# BSD 3-Clause License
#
# Copyright (c) 2026 <Sungwoo Jung, Cheng-Yu Tsai, Amaan Rahman, Junsik Yoon, Sandra Maria Shaji, Sung Kyu Lim >, University of Southern California
#
# Redistribution and use in source and binary forms, with or without
# modification, are permitted under the BSD 3-Clause License.
# See the LICENSE file in the project root for full license terms.


VERSION 5.8 ;
BUSBITCHARS "[]" ;
DIVIDERCHAR "/" ;

UNITS
  DATABASE MICRONS 10000 ;
END UNITS

MANUFACTURINGGRID 0.0001 ;

PROPERTYDEFINITIONS
  MACRO snapMode STRING ;
  MACRO segSnapMode STRING ;
  MACRO dimmingIntensity INTEGER ;
  MACRO arrayDisplay STRING ;
  MACRO displayResolution STRING ;
  MACRO instanceDrawingMode STRING ;
  MACRO autoZoomScale INTEGER ;
  MACRO filterSizeDrawingStyle STRING ;
  MACRO dimmingScope STRING ;
  MACRO filterSize REAL ;
  MACRO scrollPercent INTEGER ;
  MACRO gridMultiple INTEGER ;
  MACRO gridSpacing REAL ;
  MACRO xSnapSpacing REAL ;
  MACRO instLabel STRING ;
  MACRO autoZoomMode STRING ;
  MACRO lppVisibilityMode STRING ;
  MACRO stopLevel INTEGER ;
  MACRO mergeScope STRING ;
  MACRO ySnapSpacing REAL ;
  MACRO startLevel INTEGER ;
  MACRO pathCL STRING ;
END PROPERTYDEFINITIONS

LAYER well
  TYPE MASTERSLICE ;
END well

LAYER Gate
  TYPE MASTERSLICE ;
END Gate

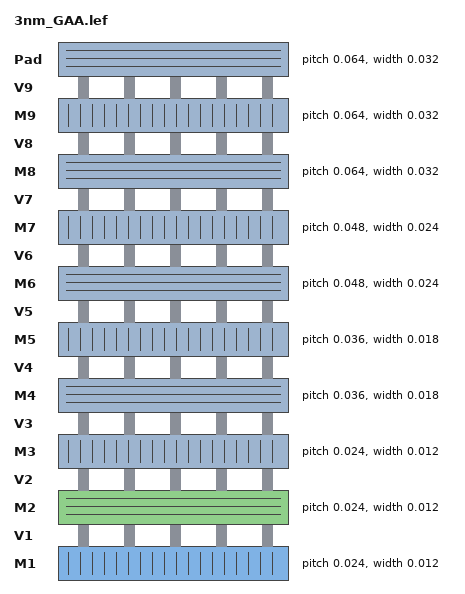
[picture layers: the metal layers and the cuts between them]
LAYER M1
  TYPE ROUTING ;
  DIRECTION VERTICAL ;
  PITCH 0.024 ;
  WIDTH 0.012 ;
  PROPERTY LEF58_WIDTH "WIDTH 0.012 WRONGDIRECTION ;" ;
END M1

LAYER V1
  TYPE CUT ;
END V1

LAYER M2
  TYPE ROUTING ;
  DIRECTION HORIZONTAL ;
  PITCH 0.024 ;
  WIDTH 0.012 ;
  PROPERTY LEF58_WIDTH "WIDTH 0.012 WRONGDIRECTION ;" ;
END M2

LAYER V2
  TYPE CUT ;
END V2

LAYER M3
  TYPE ROUTING ;
  DIRECTION VERTICAL ;
  PITCH 0.024 ;
  WIDTH 0.012 ;
  PROPERTY LEF58_WIDTH "WIDTH 0.012 WRONGDIRECTION ;" ;
END M3

LAYER V3
  TYPE CUT ;
END V3

LAYER M4
  TYPE ROUTING ;
  DIRECTION HORIZONTAL ;
  PITCH 0.036 ;
  WIDTH 0.018 ;
  PROPERTY LEF58_WIDTH "WIDTH 0.018 WRONGDIRECTION ;" ;
END M4

LAYER V4
  TYPE CUT ;
END V4

LAYER M5
  TYPE ROUTING ;
  DIRECTION VERTICAL ;
  PITCH 0.036 ;
  WIDTH 0.018 ;
  PROPERTY LEF58_WIDTH "WIDTH 0.018 WRONGDIRECTION ;" ;
END M5

LAYER V5
  TYPE CUT ;
END V5

LAYER M6
  TYPE ROUTING ;
  DIRECTION HORIZONTAL ;
  PITCH 0.048 ;
  WIDTH 0.024 ;
  PROPERTY LEF58_WIDTH "WIDTH 0.024 WRONGDIRECTION ;" ;
END M6

LAYER V6
  TYPE CUT ;
END V6

LAYER M7
  TYPE ROUTING ;
  DIRECTION VERTICAL ;
  PITCH 0.048 ;
  WIDTH 0.024 ;
  PROPERTY LEF58_WIDTH "WIDTH 0.024 WRONGDIRECTION ;" ;
END M7

LAYER V7
  TYPE CUT ;
END V7

LAYER M8
  TYPE ROUTING ;
  DIRECTION HORIZONTAL ;
  PITCH 0.064 ;
  WIDTH 0.032 ;
  PROPERTY LEF58_WIDTH "WIDTH 0.032 WRONGDIRECTION ;" ;
END M8

LAYER V8
  TYPE CUT ;
END V8

LAYER M9
  TYPE ROUTING ;
  DIRECTION VERTICAL ;
  PITCH 0.064 ;
  WIDTH 0.032 ;
  PROPERTY LEF58_WIDTH "WIDTH 0.032 WRONGDIRECTION ;" ;
END M9

LAYER V9
  TYPE CUT ;
END V9

LAYER Pad
  TYPE ROUTING ;
  DIRECTION HORIZONTAL ;
  PITCH 0.064 ;
  WIDTH 0.032 ;
  PROPERTY LEF58_WIDTH "WIDTH 0.032 WRONGDIRECTION ;" ;
END Pad

LAYER Active
  TYPE MASTERSLICE ;
END Active

LAYER fin
  TYPE MASTERSLICE ;
END fin

LAYER P_SUB
  TYPE MASTERSLICE ;
END P_SUB

LAYER Dummy
  TYPE MASTERSLICE ;
END Dummy

LAYER GCut
  TYPE MASTERSLICE ;
END GCut

LAYER Nselect
  TYPE MASTERSLICE ;
END Nselect

LAYER Pselect
  TYPE MASTERSLICE ;
END Pselect

LAYER SDT
  TYPE MASTERSLICE ;
END SDT

LAYER LIG
  TYPE MASTERSLICE ;
END LIG

LAYER LISD
  TYPE MASTERSLICE ;
END LISD

LAYER V0
  TYPE MASTERSLICE ;
END V0

LAYER SLVT
  TYPE MASTERSLICE ;
END SLVT

LAYER LVT
  TYPE MASTERSLICE ;
END LVT

LAYER SRAMDRC
  TYPE MASTERSLICE ;
END SRAMDRC

LAYER BOUNDARY
  TYPE MASTERSLICE ;
END BOUNDARY

LAYER TEXT
  TYPE MASTERSLICE ;
END TEXT

LAYER SRAMVT
  TYPE MASTERSLICE ;
END SRAMVT

LAYER text
  TYPE MASTERSLICE ;
END text

VIA Pad_M9
  LAYER M9 ;
    RECT -0.016 -0.025 0.016 0.025 ;
  LAYER V9 ;
    RECT -0.016 -0.016 0.016 0.016 ;
  LAYER Pad ;
    RECT -0.027 -0.016 0.027 0.016 ;
END Pad_M9

VIA M9_M8
  LAYER M8 ;
    RECT -0.025 -0.016 0.025 0.016 ;
  LAYER V8 ;
    RECT -0.016 -0.016 0.016 0.016 ;
  LAYER M9 ;
    RECT -0.016 -0.025 0.016 0.025 ;
END M9_M8

VIA M8_M7
  LAYER M7 ;
    RECT -0.012 -0.019 0.012 0.019 ;
  LAYER V7 ;
    RECT -0.012 -0.012 0.012 0.012 ;
  LAYER M8 ;
    RECT -0.021 -0.012 0.021 0.012 ;
END M8_M7

VIA M7_M6
  LAYER M6 ;
    RECT -0.019 -0.012 0.019 0.012 ;
  LAYER V6 ;
    RECT -0.012 -0.012 0.012 0.012 ;
  LAYER M7 ;
    RECT -0.012 -0.019 0.012 0.019 ;
END M7_M6

VIA M6_M5
  LAYER M5 ;
    RECT -0.009 -0.014 0.009 0.014 ;
  LAYER V5 ;
    RECT -0.009 -0.009 0.009 0.009 ;
  LAYER M6 ;
    RECT -0.016 -0.009 0.016 0.009 ;
END M6_M5

VIA M5_M4
  LAYER M4 ;
    RECT -0.014 -0.009 0.014 0.009 ;
  LAYER V4 ;
    RECT -0.009 -0.009 0.009 0.009 ;
  LAYER M5 ;
    RECT -0.009 -0.014 0.009 0.014 ;
END M5_M4

VIA M4_M3
  LAYER M3 ;
    RECT -0.006 -0.009 0.006 0.009 ;
  LAYER V3 ;
    RECT -0.006 -0.006 0.006 0.006 ;
  LAYER M4 ;
    RECT -0.011 -0.006 0.011 0.006 ;
END M4_M3

VIA M3_M2
  LAYER M2 ;
    RECT -0.009 -0.006 0.009 0.006 ;
  LAYER V2 ;
    RECT -0.006 -0.006 0.006 0.006 ;
  LAYER M3 ;
    RECT -0.006 -0.009 0.006 0.009 ;
END M3_M2

VIA M2_M1
  LAYER M1 ;
    RECT -0.006 -0.009 0.006 0.009 ;
  LAYER V1 ;
    RECT -0.006 -0.006 0.006 0.006 ;
  LAYER M2 ;
    RECT -0.009 -0.006 0.009 0.006 ;
END M2_M1

SITE core
  CLASS CORE ;
  SIZE 0.042 BY 0.144 ;
END core

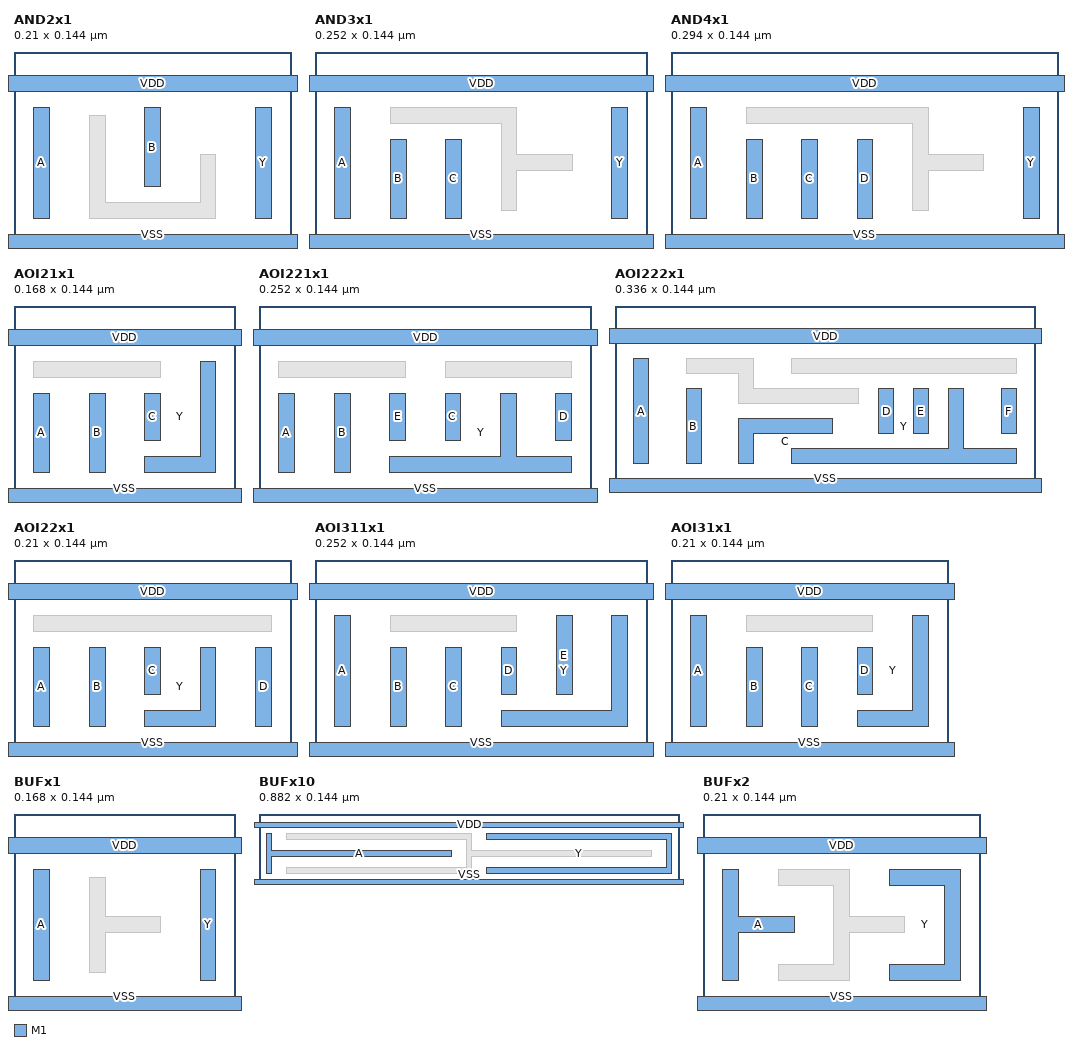
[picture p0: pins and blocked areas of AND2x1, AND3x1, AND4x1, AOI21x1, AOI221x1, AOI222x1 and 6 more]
MACRO AND2x1
  CLASS CORE ;
  FOREIGN AND2x1 ;
  ORIGIN 0 0 ;
  SIZE 0.21 BY 0.144 ;
  SYMMETRY X Y ;
  SITE core ;
  PIN A
    DIRECTION INPUT ;
    USE SIGNAL ;
    PORT
      LAYER M1 ;
        RECT 0.015 0.018 0.027 0.102 ;
    END
  END A
  PIN B
    DIRECTION INPUT ;
    USE SIGNAL ;
    PORT
      LAYER M1 ;
        RECT 0.099 0.042 0.111 0.102 ;
    END
  END B
  PIN Y
    DIRECTION OUTPUT ;
    USE SIGNAL ;
    PORT
      LAYER M1 ;
        RECT 0.183 0.018 0.195 0.102 ;
    END
  END Y
  PIN VDD
    DIRECTION INOUT ;
    USE POWER ;
    PORT
      LAYER M1 ;
        RECT -0.009 0.114 0.219 0.126 ;
    END
  END VDD
  PIN VSS
    DIRECTION INOUT ;
    USE GROUND ;
    PORT
      LAYER M1 ;
        RECT -0.009 -0.006 0.219 0.006 ;
    END
  END VSS
  OBS
    LAYER M1 ;
      POLYGON 0.069 0.096 0.069 0.03 0.141 0.03 0.141 0.066 0.153 0.066 0.153 0.018 0.057 0.018 0.057 0.096 ;
  END
END AND2x1

MACRO AND3x1
  CLASS CORE ;
  FOREIGN AND3x1 ;
  ORIGIN 0 0 ;
  SIZE 0.252 BY 0.144 ;
  SYMMETRY X Y ;
  SITE core ;
  PIN A
    DIRECTION INPUT ;
    USE SIGNAL ;
    PORT
      LAYER M1 ;
        RECT 0.015 0.018 0.027 0.102 ;
    END
  END A
  PIN B
    DIRECTION INPUT ;
    USE SIGNAL ;
    PORT
      LAYER M1 ;
        RECT 0.057 0.018 0.069 0.078 ;
    END
  END B
  PIN C
    DIRECTION INPUT ;
    USE SIGNAL ;
    PORT
      LAYER M1 ;
        RECT 0.099 0.018 0.111 0.078 ;
    END
  END C
  PIN Y
    DIRECTION OUTPUT ;
    USE SIGNAL ;
    PORT
      LAYER M1 ;
        RECT 0.225 0.018 0.237 0.102 ;
    END
  END Y
  PIN VDD
    DIRECTION INOUT ;
    USE POWER ;
    PORT
      LAYER M1 ;
        RECT -0.009 0.114 0.261 0.126 ;
    END
  END VDD
  PIN VSS
    DIRECTION INOUT ;
    USE GROUND ;
    PORT
      LAYER M1 ;
        RECT -0.009 -0.006 0.261 0.006 ;
    END
  END VSS
  OBS
    LAYER M1 ;
      POLYGON 0.153 0.102 0.153 0.066 0.195 0.066 0.195 0.054 0.153 0.054 0.153 0.024 0.141 0.024 0.141 0.09 0.057 0.09 0.057 0.102 ;
  END
END AND3x1

MACRO AND4x1
  CLASS CORE ;
  FOREIGN AND4x1 ;
  ORIGIN 0 0 ;
  SIZE 0.294 BY 0.144 ;
  SYMMETRY X Y ;
  SITE core ;
  PIN A
    DIRECTION INPUT ;
    USE SIGNAL ;
    PORT
      LAYER M1 ;
        RECT 0.015 0.018 0.027 0.102 ;
    END
  END A
  PIN B
    DIRECTION INPUT ;
    USE SIGNAL ;
    PORT
      LAYER M1 ;
        RECT 0.057 0.018 0.069 0.078 ;
    END
  END B
  PIN C
    DIRECTION INPUT ;
    USE SIGNAL ;
    PORT
      LAYER M1 ;
        RECT 0.099 0.018 0.111 0.078 ;
    END
  END C
  PIN D
    DIRECTION INPUT ;
    USE SIGNAL ;
    PORT
      LAYER M1 ;
        RECT 0.141 0.018 0.153 0.078 ;
    END
  END D
  PIN Y
    DIRECTION OUTPUT ;
    USE SIGNAL ;
    PORT
      LAYER M1 ;
        RECT 0.267 0.018 0.279 0.102 ;
    END
  END Y
  PIN VDD
    DIRECTION INOUT ;
    USE POWER ;
    PORT
      LAYER M1 ;
        RECT -0.009 0.114 0.303 0.126 ;
    END
  END VDD
  PIN VSS
    DIRECTION INOUT ;
    USE GROUND ;
    PORT
      LAYER M1 ;
        RECT -0.009 -0.006 0.303 0.006 ;
    END
  END VSS
  OBS
    LAYER M1 ;
      POLYGON 0.195 0.102 0.195 0.066 0.237 0.066 0.237 0.054 0.195 0.054 0.195 0.024 0.183 0.024 0.183 0.09 0.057 0.09 0.057 0.102 ;
  END
END AND4x1

MACRO AOI21x1
  CLASS CORE ;
  FOREIGN AOI21x1 ;
  ORIGIN 0 0 ;
  SIZE 0.168 BY 0.144 ;
  SYMMETRY X Y ;
  SITE core ;
  PIN A
    DIRECTION INPUT ;
    USE SIGNAL ;
    PORT
      LAYER M1 ;
        RECT 0.015 0.018 0.027 0.078 ;
    END
  END A
  PIN B
    DIRECTION INPUT ;
    USE SIGNAL ;
    PORT
      LAYER M1 ;
        RECT 0.057 0.018 0.069 0.078 ;
    END
  END B
  PIN C
    DIRECTION INPUT ;
    USE SIGNAL ;
    PORT
      LAYER M1 ;
        RECT 0.099 0.042 0.111 0.078 ;
    END
  END C
  PIN Y
    DIRECTION OUTPUT ;
    USE SIGNAL ;
    PORT
      LAYER M1 ;
        POLYGON 0.153 0.102 0.153 0.018 0.099 0.018 0.099 0.03 0.141 0.03 0.141 0.102 ;
    END
  END Y
  PIN VDD
    DIRECTION INOUT ;
    USE POWER ;
    PORT
      LAYER M1 ;
        RECT -0.009 0.114 0.177 0.126 ;
    END
  END VDD
  PIN VSS
    DIRECTION INOUT ;
    USE GROUND ;
    PORT
      LAYER M1 ;
        RECT -0.009 -0.006 0.177 0.006 ;
    END
  END VSS
  OBS
    LAYER M1 ;
      RECT 0.015 0.09 0.111 0.102 ;
  END
END AOI21x1

MACRO AOI221x1
  CLASS CORE ;
  FOREIGN AOI221x1 ;
  ORIGIN 0 0 ;
  SIZE 0.252 BY 0.144 ;
  SYMMETRY X Y ;
  SITE core ;
  PIN A
    DIRECTION INPUT ;
    USE SIGNAL ;
    PORT
      LAYER M1 ;
        RECT 0.015 0.018 0.027 0.078 ;
    END
  END A
  PIN B
    DIRECTION INPUT ;
    USE SIGNAL ;
    PORT
      LAYER M1 ;
        RECT 0.057 0.018 0.069 0.078 ;
    END
  END B
  PIN C
    DIRECTION INPUT ;
    USE SIGNAL ;
    PORT
      LAYER M1 ;
        RECT 0.141 0.042 0.153 0.078 ;
    END
  END C
  PIN D
    DIRECTION INPUT ;
    USE SIGNAL ;
    PORT
      LAYER M1 ;
        RECT 0.225 0.042 0.237 0.078 ;
    END
  END D
  PIN E
    DIRECTION INPUT ;
    USE SIGNAL ;
    PORT
      LAYER M1 ;
        RECT 0.099 0.042 0.111 0.078 ;
    END
  END E
  PIN Y
    DIRECTION OUTPUT ;
    USE SIGNAL ;
    PORT
      LAYER M1 ;
        POLYGON 0.195 0.078 0.195 0.03 0.237 0.03 0.237 0.018 0.099 0.018 0.099 0.03 0.183 0.03 0.183 0.078 ;
    END
  END Y
  PIN VDD
    DIRECTION INOUT ;
    USE POWER ;
    PORT
      LAYER M1 ;
        RECT -0.009 0.114 0.261 0.126 ;
    END
  END VDD
  PIN VSS
    DIRECTION INOUT ;
    USE GROUND ;
    PORT
      LAYER M1 ;
        RECT -0.009 -0.006 0.261 0.006 ;
    END
  END VSS
  OBS
    LAYER M1 ;
      RECT 0.141 0.09 0.237 0.102 ;
      RECT 0.015 0.09 0.111 0.102 ;
  END
END AOI221x1

MACRO AOI222x1
  CLASS CORE ;
  FOREIGN AOI222x1 ;
  ORIGIN 0 0 ;
  SIZE 0.336 BY 0.144 ;
  SYMMETRY X Y ;
  SITE core ;
  PIN A
    DIRECTION INPUT ;
    USE SIGNAL ;
    PORT
      LAYER M1 ;
        RECT 0.015 0.018 0.027 0.102 ;
    END
  END A
  PIN B
    DIRECTION INPUT ;
    USE SIGNAL ;
    PORT
      LAYER M1 ;
        RECT 0.057 0.018 0.069 0.078 ;
    END
  END B
  PIN C
    DIRECTION INPUT ;
    USE SIGNAL ;
    PORT
      LAYER M1 ;
        POLYGON 0.174 0.054 0.174 0.042 0.111 0.042 0.111 0.018 0.099 0.018 0.099 0.054 ;
    END
  END C
  PIN D
    DIRECTION INPUT ;
    USE SIGNAL ;
    PORT
      LAYER M1 ;
        RECT 0.211 0.042 0.223 0.078 ;
    END
  END D
  PIN E
    DIRECTION INPUT ;
    USE SIGNAL ;
    PORT
      LAYER M1 ;
        RECT 0.239 0.042 0.251 0.078 ;
    END
  END E
  PIN F
    DIRECTION INPUT ;
    USE SIGNAL ;
    PORT
      LAYER M1 ;
        RECT 0.309 0.042 0.321 0.078 ;
    END
  END F
  PIN Y
    DIRECTION OUTPUT ;
    USE SIGNAL ;
    PORT
      LAYER M1 ;
        POLYGON 0.279 0.078 0.279 0.03 0.321 0.03 0.321 0.018 0.141 0.018 0.141 0.03 0.267 0.03 0.267 0.078 ;
    END
  END Y
  PIN VDD
    DIRECTION INOUT ;
    USE POWER ;
    PORT
      LAYER M1 ;
        RECT -0.009 0.114 0.345 0.126 ;
    END
  END VDD
  PIN VSS
    DIRECTION INOUT ;
    USE GROUND ;
    PORT
      LAYER M1 ;
        RECT -0.009 -0.006 0.345 0.006 ;
    END
  END VSS
  OBS
    LAYER M1 ;
      RECT 0.141 0.09 0.321 0.102 ;
      POLYGON 0.111 0.102 0.111 0.078 0.195 0.078 0.195 0.066 0.099 0.066 0.099 0.09 0.057 0.09 0.057 0.102 ;
  END
END AOI222x1

MACRO AOI22x1
  CLASS CORE ;
  FOREIGN AOI22x1 ;
  ORIGIN 0 0 ;
  SIZE 0.21 BY 0.144 ;
  SYMMETRY X Y ;
  SITE core ;
  PIN A
    DIRECTION INPUT ;
    USE SIGNAL ;
    PORT
      LAYER M1 ;
        RECT 0.015 0.018 0.027 0.078 ;
    END
  END A
  PIN B
    DIRECTION INPUT ;
    USE SIGNAL ;
    PORT
      LAYER M1 ;
        RECT 0.057 0.018 0.069 0.078 ;
    END
  END B
  PIN C
    DIRECTION INPUT ;
    USE SIGNAL ;
    PORT
      LAYER M1 ;
        RECT 0.099 0.042 0.111 0.078 ;
    END
  END C
  PIN D
    DIRECTION INPUT ;
    USE SIGNAL ;
    PORT
      LAYER M1 ;
        RECT 0.183 0.018 0.195 0.078 ;
    END
  END D
  PIN Y
    DIRECTION OUTPUT ;
    USE SIGNAL ;
    PORT
      LAYER M1 ;
        POLYGON 0.153 0.078 0.153 0.018 0.099 0.018 0.099 0.03 0.141 0.03 0.141 0.078 ;
    END
  END Y
  PIN VDD
    DIRECTION INOUT ;
    USE POWER ;
    PORT
      LAYER M1 ;
        RECT -0.009 0.114 0.219 0.126 ;
    END
  END VDD
  PIN VSS
    DIRECTION INOUT ;
    USE GROUND ;
    PORT
      LAYER M1 ;
        RECT -0.009 -0.006 0.219 0.006 ;
    END
  END VSS
  OBS
    LAYER M1 ;
      RECT 0.015 0.09 0.195 0.102 ;
  END
END AOI22x1

MACRO AOI311x1
  CLASS CORE ;
  FOREIGN AOI311x1 ;
  ORIGIN 0 0 ;
  SIZE 0.252 BY 0.144 ;
  SYMMETRY X Y ;
  SITE core ;
  PIN A
    DIRECTION INPUT ;
    USE SIGNAL ;
    PORT
      LAYER M1 ;
        RECT 0.015 0.018 0.027 0.102 ;
    END
  END A
  PIN B
    DIRECTION INPUT ;
    USE SIGNAL ;
    PORT
      LAYER M1 ;
        RECT 0.057 0.018 0.069 0.078 ;
    END
  END B
  PIN C
    DIRECTION INPUT ;
    USE SIGNAL ;
    PORT
      LAYER M1 ;
        RECT 0.099 0.018 0.111 0.078 ;
    END
  END C
  PIN D
    DIRECTION INPUT ;
    USE SIGNAL ;
    PORT
      LAYER M1 ;
        RECT 0.141 0.042 0.153 0.078 ;
    END
  END D
  PIN E
    DIRECTION INPUT ;
    USE SIGNAL ;
    PORT
      LAYER M1 ;
        RECT 0.183 0.042 0.195 0.102 ;
    END
  END E
  PIN Y
    DIRECTION OUTPUT ;
    USE SIGNAL ;
    PORT
      LAYER M1 ;
        POLYGON 0.237 0.102 0.237 0.018 0.141 0.018 0.141 0.03 0.225 0.03 0.225 0.102 ;
    END
  END Y
  PIN VDD
    DIRECTION INOUT ;
    USE POWER ;
    PORT
      LAYER M1 ;
        RECT -0.009 0.114 0.261 0.126 ;
    END
  END VDD
  PIN VSS
    DIRECTION INOUT ;
    USE GROUND ;
    PORT
      LAYER M1 ;
        RECT -0.009 -0.006 0.261 0.006 ;
    END
  END VSS
  OBS
    LAYER M1 ;
      RECT 0.057 0.09 0.153 0.102 ;
  END
END AOI311x1

MACRO AOI31x1
  CLASS CORE ;
  FOREIGN AOI31x1 ;
  ORIGIN 0 0 ;
  SIZE 0.21 BY 0.144 ;
  SYMMETRY X Y ;
  SITE core ;
  PIN A
    DIRECTION INPUT ;
    USE SIGNAL ;
    PORT
      LAYER M1 ;
        RECT 0.015 0.018 0.027 0.102 ;
    END
  END A
  PIN B
    DIRECTION INPUT ;
    USE SIGNAL ;
    PORT
      LAYER M1 ;
        RECT 0.057 0.018 0.069 0.078 ;
    END
  END B
  PIN C
    DIRECTION INPUT ;
    USE SIGNAL ;
    PORT
      LAYER M1 ;
        RECT 0.099 0.018 0.111 0.078 ;
    END
  END C
  PIN D
    DIRECTION INPUT ;
    USE SIGNAL ;
    PORT
      LAYER M1 ;
        RECT 0.141 0.042 0.153 0.078 ;
    END
  END D
  PIN Y
    DIRECTION OUTPUT ;
    USE SIGNAL ;
    PORT
      LAYER M1 ;
        POLYGON 0.195 0.102 0.195 0.018 0.141 0.018 0.141 0.03 0.183 0.03 0.183 0.102 ;
    END
  END Y
  PIN VDD
    DIRECTION INOUT ;
    USE POWER ;
    PORT
      LAYER M1 ;
        RECT -0.009 0.114 0.219 0.126 ;
    END
  END VDD
  PIN VSS
    DIRECTION INOUT ;
    USE GROUND ;
    PORT
      LAYER M1 ;
        RECT -0.009 -0.006 0.219 0.006 ;
    END
  END VSS
  OBS
    LAYER M1 ;
      RECT 0.057 0.09 0.153 0.102 ;
  END
END AOI31x1

MACRO BUFx1
  CLASS CORE ;
  FOREIGN BUFx1 ;
  ORIGIN 0 0 ;
  SIZE 0.168 BY 0.144 ;
  SYMMETRY X Y ;
  SITE core ;
  PIN A
    DIRECTION INPUT ;
    USE SIGNAL ;
    PORT
      LAYER M1 ;
        RECT 0.015 0.018 0.027 0.102 ;
    END
  END A
  PIN Y
    DIRECTION OUTPUT ;
    USE SIGNAL ;
    PORT
      LAYER M1 ;
        RECT 0.141 0.018 0.153 0.102 ;
    END
  END Y
  PIN VDD
    DIRECTION INOUT ;
    USE POWER ;
    PORT
      LAYER M1 ;
        RECT -0.009 0.114 0.177 0.126 ;
    END
  END VDD
  PIN VSS
    DIRECTION INOUT ;
    USE GROUND ;
    PORT
      LAYER M1 ;
        RECT -0.009 -0.006 0.177 0.006 ;
    END
  END VSS
  OBS
    LAYER M1 ;
      POLYGON 0.069 0.096 0.069 0.066 0.111 0.066 0.111 0.054 0.069 0.054 0.069 0.024 0.057 0.024 0.057 0.096 ;
  END
END BUFx1

MACRO BUFx10
  CLASS CORE ;
  FOREIGN BUFx10 ;
  ORIGIN 0 0 ;
  SIZE 0.882 BY 0.144 ;
  SYMMETRY X Y ;
  SITE core ;
  PIN A
    DIRECTION INPUT ;
    USE SIGNAL ;
    PORT
      LAYER M1 ;
        POLYGON 0.027 0.102 0.027 0.066 0.405 0.066 0.405 0.054 0.027 0.054 0.027 0.018 0.015 0.018 0.015 0.102 ;
    END
  END A
  PIN Y
    DIRECTION OUTPUT ;
    USE SIGNAL ;
    PORT
      LAYER M1 ;
        POLYGON 0.867 0.102 0.867 0.018 0.477 0.018 0.477 0.03 0.855 0.03 0.855 0.09 0.477 0.09 0.477 0.102 ;
    END
  END Y
  PIN VDD
    DIRECTION INOUT ;
    USE POWER ;
    PORT
      LAYER M1 ;
        RECT -0.009 0.114 0.891 0.126 ;
    END
  END VDD
  PIN VSS
    DIRECTION INOUT ;
    USE GROUND ;
    PORT
      LAYER M1 ;
        RECT -0.009 -0.006 0.891 0.006 ;
    END
  END VSS
  OBS
    LAYER M1 ;
      POLYGON 0.447 0.102 0.447 0.066 0.825 0.066 0.825 0.054 0.447 0.054 0.447 0.018 0.057 0.018 0.057 0.03 0.435 0.03 0.435 0.09 0.057 0.09 0.057 0.102 ;
  END
  PROPERTY stopLevel 0 ;
  PROPERTY startLevel 0 ;
  PROPERTY snapMode "orthogonal" ;
  PROPERTY segSnapMode "orthogonal" ;
  PROPERTY pathCL "yes" ;
  PROPERTY lppVisibilityMode "donotCheckValidity" ;
  PROPERTY instanceDrawingMode "BBox" ;
  PROPERTY autoZoomScale 90 ;
  PROPERTY gridSpacing 1 ;
  PROPERTY xSnapSpacing 0.001 ;
  PROPERTY autoZoomMode "Pan" ;
  PROPERTY mergeScope "pcells" ;
  PROPERTY gridMultiple 5 ;
  PROPERTY arrayDisplay "Full" ;
  PROPERTY scrollPercent 25 ;
  PROPERTY displayResolution "Medium" ;
  PROPERTY instLabel "master" ;
  PROPERTY ySnapSpacing 0.001 ;
  PROPERTY filterSize 6 ;
  PROPERTY dimmingIntensity 50 ;
  PROPERTY filterSizeDrawingStyle "empty" ;
  PROPERTY dimmingScope "none" ;
END BUFx10

MACRO BUFx2
  CLASS CORE ;
  FOREIGN BUFx2 ;
  ORIGIN 0 0 ;
  SIZE 0.21 BY 0.144 ;
  SYMMETRY X Y ;
  SITE core ;
  PIN A
    DIRECTION INPUT ;
    USE SIGNAL ;
    PORT
      LAYER M1 ;
        POLYGON 0.027 0.102 0.027 0.066 0.069 0.066 0.069 0.054 0.027 0.054 0.027 0.018 0.015 0.018 0.015 0.102 ;
    END
  END A
  PIN Y
    DIRECTION OUTPUT ;
    USE SIGNAL ;
    PORT
      LAYER M1 ;
        POLYGON 0.195 0.102 0.195 0.018 0.141 0.018 0.141 0.03 0.183 0.03 0.183 0.09 0.141 0.09 0.141 0.102 ;
    END
  END Y
  PIN VDD
    DIRECTION INOUT ;
    USE POWER ;
    PORT
      LAYER M1 ;
        RECT -0.009 0.114 0.219 0.126 ;
    END
  END VDD
  PIN VSS
    DIRECTION INOUT ;
    USE GROUND ;
    PORT
      LAYER M1 ;
        RECT -0.009 -0.006 0.219 0.006 ;
    END
  END VSS
  OBS
    LAYER M1 ;
      POLYGON 0.111 0.102 0.111 0.066 0.153 0.066 0.153 0.054 0.111 0.054 0.111 0.018 0.057 0.018 0.057 0.03 0.099 0.03 0.099 0.09 0.057 0.09 0.057 0.102 ;
  END
END BUFx2

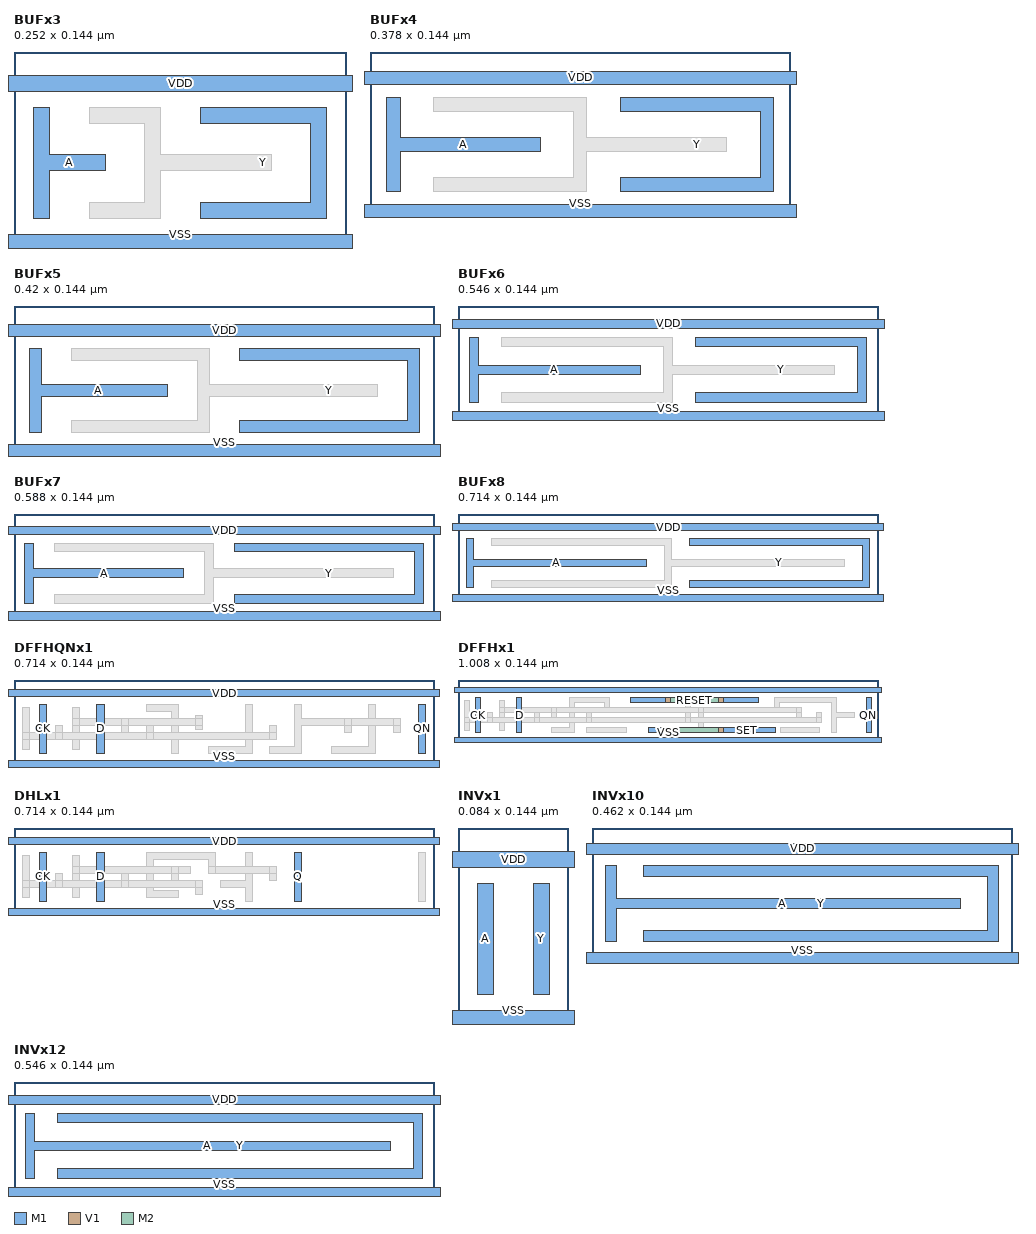
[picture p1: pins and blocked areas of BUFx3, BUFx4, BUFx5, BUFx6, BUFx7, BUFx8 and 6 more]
MACRO BUFx3
  CLASS CORE ;
  FOREIGN BUFx3 ;
  ORIGIN 0 0 ;
  SIZE 0.252 BY 0.144 ;
  SYMMETRY X Y ;
  SITE core ;
  PIN A
    DIRECTION INPUT ;
    USE SIGNAL ;
    PORT
      LAYER M1 ;
        POLYGON 0.027 0.102 0.027 0.066 0.069 0.066 0.069 0.054 0.027 0.054 0.027 0.018 0.015 0.018 0.015 0.102 ;
    END
  END A
  PIN Y
    DIRECTION OUTPUT ;
    USE SIGNAL ;
    PORT
      LAYER M1 ;
        POLYGON 0.237 0.102 0.237 0.018 0.141 0.018 0.141 0.03 0.225 0.03 0.225 0.09 0.141 0.09 0.141 0.102 ;
    END
  END Y
  PIN VDD
    DIRECTION INOUT ;
    USE POWER ;
    PORT
      LAYER M1 ;
        RECT -0.009 0.114 0.261 0.126 ;
    END
  END VDD
  PIN VSS
    DIRECTION INOUT ;
    USE GROUND ;
    PORT
      LAYER M1 ;
        RECT -0.009 -0.006 0.261 0.006 ;
    END
  END VSS
  OBS
    LAYER M1 ;
      POLYGON 0.111 0.102 0.111 0.066 0.195 0.066 0.195 0.054 0.111 0.054 0.111 0.018 0.057 0.018 0.057 0.03 0.099 0.03 0.099 0.09 0.057 0.09 0.057 0.102 ;
  END
  PROPERTY stopLevel 0 ;
  PROPERTY startLevel 0 ;
  PROPERTY snapMode "orthogonal" ;
  PROPERTY segSnapMode "orthogonal" ;
  PROPERTY pathCL "yes" ;
  PROPERTY lppVisibilityMode "donotCheckValidity" ;
  PROPERTY instanceDrawingMode "BBox" ;
  PROPERTY autoZoomScale 90 ;
  PROPERTY gridSpacing 1 ;
  PROPERTY xSnapSpacing 0.001 ;
  PROPERTY autoZoomMode "Pan" ;
  PROPERTY mergeScope "pcells" ;
  PROPERTY gridMultiple 5 ;
  PROPERTY arrayDisplay "Full" ;
  PROPERTY scrollPercent 25 ;
  PROPERTY displayResolution "Medium" ;
  PROPERTY instLabel "master" ;
  PROPERTY ySnapSpacing 0.001 ;
  PROPERTY filterSize 6 ;
  PROPERTY dimmingIntensity 50 ;
  PROPERTY filterSizeDrawingStyle "empty" ;
  PROPERTY dimmingScope "none" ;
END BUFx3

MACRO BUFx4
  CLASS CORE ;
  FOREIGN BUFx4 ;
  ORIGIN 0 0 ;
  SIZE 0.378 BY 0.144 ;
  SYMMETRY X Y ;
  SITE core ;
  PIN A
    DIRECTION INPUT ;
    USE SIGNAL ;
    PORT
      LAYER M1 ;
        POLYGON 0.027 0.102 0.027 0.066 0.153 0.066 0.153 0.054 0.027 0.054 0.027 0.018 0.015 0.018 0.015 0.102 ;
    END
  END A
  PIN Y
    DIRECTION OUTPUT ;
    USE SIGNAL ;
    PORT
      LAYER M1 ;
        POLYGON 0.363 0.102 0.363 0.018 0.225 0.018 0.225 0.03 0.351 0.03 0.351 0.09 0.225 0.09 0.225 0.102 ;
    END
  END Y
  PIN VDD
    DIRECTION INOUT ;
    USE POWER ;
    PORT
      LAYER M1 ;
        RECT -0.009 0.114 0.387 0.126 ;
    END
  END VDD
  PIN VSS
    DIRECTION INOUT ;
    USE GROUND ;
    PORT
      LAYER M1 ;
        RECT -0.009 -0.006 0.387 0.006 ;
    END
  END VSS
  OBS
    LAYER M1 ;
      POLYGON 0.195 0.102 0.195 0.066 0.321 0.066 0.321 0.054 0.195 0.054 0.195 0.018 0.057 0.018 0.057 0.03 0.183 0.03 0.183 0.09 0.057 0.09 0.057 0.102 ;
  END
  PROPERTY stopLevel 0 ;
  PROPERTY startLevel 0 ;
  PROPERTY snapMode "orthogonal" ;
  PROPERTY segSnapMode "orthogonal" ;
  PROPERTY pathCL "yes" ;
  PROPERTY lppVisibilityMode "donotCheckValidity" ;
  PROPERTY instanceDrawingMode "BBox" ;
  PROPERTY autoZoomScale 90 ;
  PROPERTY gridSpacing 1 ;
  PROPERTY xSnapSpacing 0.001 ;
  PROPERTY autoZoomMode "Pan" ;
  PROPERTY mergeScope "pcells" ;
  PROPERTY gridMultiple 5 ;
  PROPERTY arrayDisplay "Full" ;
  PROPERTY scrollPercent 25 ;
  PROPERTY displayResolution "Medium" ;
  PROPERTY instLabel "master" ;
  PROPERTY ySnapSpacing 0.001 ;
  PROPERTY filterSize 6 ;
  PROPERTY dimmingIntensity 50 ;
  PROPERTY filterSizeDrawingStyle "empty" ;
  PROPERTY dimmingScope "none" ;
END BUFx4

MACRO BUFx5
  CLASS CORE ;
  FOREIGN BUFx5 ;
  ORIGIN 0 0 ;
  SIZE 0.42 BY 0.144 ;
  SYMMETRY X Y ;
  SITE core ;
  PIN A
    DIRECTION INPUT ;
    USE SIGNAL ;
    PORT
      LAYER M1 ;
        POLYGON 0.027 0.102 0.027 0.066 0.153 0.066 0.153 0.054 0.027 0.054 0.027 0.018 0.015 0.018 0.015 0.102 ;
    END
  END A
  PIN Y
    DIRECTION OUTPUT ;
    USE SIGNAL ;
    PORT
      LAYER M1 ;
        POLYGON 0.405 0.102 0.405 0.018 0.225 0.018 0.225 0.03 0.393 0.03 0.393 0.09 0.225 0.09 0.225 0.102 ;
    END
  END Y
  PIN VDD
    DIRECTION INOUT ;
    USE POWER ;
    PORT
      LAYER M1 ;
        RECT -0.009 0.114 0.429 0.126 ;
    END
  END VDD
  PIN VSS
    DIRECTION INOUT ;
    USE GROUND ;
    PORT
      LAYER M1 ;
        RECT -0.009 -0.006 0.429 0.006 ;
    END
  END VSS
  OBS
    LAYER M1 ;
      POLYGON 0.195 0.102 0.195 0.066 0.363 0.066 0.363 0.054 0.195 0.054 0.195 0.018 0.057 0.018 0.057 0.03 0.183 0.03 0.183 0.09 0.057 0.09 0.057 0.102 ;
  END
  PROPERTY stopLevel 0 ;
  PROPERTY startLevel 0 ;
  PROPERTY snapMode "orthogonal" ;
  PROPERTY segSnapMode "orthogonal" ;
  PROPERTY pathCL "yes" ;
  PROPERTY lppVisibilityMode "donotCheckValidity" ;
  PROPERTY instanceDrawingMode "BBox" ;
  PROPERTY autoZoomScale 90 ;
  PROPERTY gridSpacing 1 ;
  PROPERTY xSnapSpacing 0.001 ;
  PROPERTY autoZoomMode "Pan" ;
  PROPERTY mergeScope "pcells" ;
  PROPERTY gridMultiple 5 ;
  PROPERTY arrayDisplay "Full" ;
  PROPERTY scrollPercent 25 ;
  PROPERTY displayResolution "Medium" ;
  PROPERTY instLabel "master" ;
  PROPERTY ySnapSpacing 0.001 ;
  PROPERTY filterSize 6 ;
  PROPERTY dimmingIntensity 50 ;
  PROPERTY filterSizeDrawingStyle "empty" ;
  PROPERTY dimmingScope "none" ;
END BUFx5

MACRO BUFx6
  CLASS CORE ;
  FOREIGN BUFx6 ;
  ORIGIN 0 0 ;
  SIZE 0.546 BY 0.144 ;
  SYMMETRY X Y ;
  SITE core ;
  PIN A
    DIRECTION INPUT ;
    USE SIGNAL ;
    PORT
      LAYER M1 ;
        POLYGON 0.027 0.102 0.027 0.066 0.237 0.066 0.237 0.054 0.027 0.054 0.027 0.018 0.015 0.018 0.015 0.102 ;
    END
  END A
  PIN Y
    DIRECTION OUTPUT ;
    USE SIGNAL ;
    PORT
      LAYER M1 ;
        POLYGON 0.531 0.102 0.531 0.018 0.309 0.018 0.309 0.03 0.519 0.03 0.519 0.09 0.309 0.09 0.309 0.102 ;
    END
  END Y
  PIN VDD
    DIRECTION INOUT ;
    USE POWER ;
    PORT
      LAYER M1 ;
        RECT -0.009 0.114 0.555 0.126 ;
    END
  END VDD
  PIN VSS
    DIRECTION INOUT ;
    USE GROUND ;
    PORT
      LAYER M1 ;
        RECT -0.009 -0.006 0.555 0.006 ;
    END
  END VSS
  OBS
    LAYER M1 ;
      POLYGON 0.279 0.102 0.279 0.066 0.489 0.066 0.489 0.054 0.279 0.054 0.279 0.018 0.057 0.018 0.057 0.03 0.267 0.03 0.267 0.09 0.057 0.09 0.057 0.102 ;
  END
  PROPERTY stopLevel 0 ;
  PROPERTY startLevel 0 ;
  PROPERTY snapMode "orthogonal" ;
  PROPERTY segSnapMode "orthogonal" ;
  PROPERTY pathCL "yes" ;
  PROPERTY lppVisibilityMode "donotCheckValidity" ;
  PROPERTY instanceDrawingMode "BBox" ;
  PROPERTY autoZoomScale 90 ;
  PROPERTY gridSpacing 1 ;
  PROPERTY xSnapSpacing 0.001 ;
  PROPERTY autoZoomMode "Pan" ;
  PROPERTY mergeScope "pcells" ;
  PROPERTY gridMultiple 5 ;
  PROPERTY arrayDisplay "Full" ;
  PROPERTY scrollPercent 25 ;
  PROPERTY displayResolution "Medium" ;
  PROPERTY instLabel "master" ;
  PROPERTY ySnapSpacing 0.001 ;
  PROPERTY filterSize 6 ;
  PROPERTY dimmingIntensity 50 ;
  PROPERTY filterSizeDrawingStyle "empty" ;
  PROPERTY dimmingScope "none" ;
END BUFx6

MACRO BUFx7
  CLASS CORE ;
  FOREIGN BUFx7 ;
  ORIGIN 0 0 ;
  SIZE 0.588 BY 0.144 ;
  SYMMETRY X Y ;
  SITE core ;
  PIN A
    DIRECTION INPUT ;
    USE SIGNAL ;
    PORT
      LAYER M1 ;
        POLYGON 0.027 0.102 0.027 0.066 0.237 0.066 0.237 0.054 0.027 0.054 0.027 0.018 0.015 0.018 0.015 0.102 ;
    END
  END A
  PIN Y
    DIRECTION OUTPUT ;
    USE SIGNAL ;
    PORT
      LAYER M1 ;
        POLYGON 0.573 0.102 0.573 0.018 0.309 0.018 0.309 0.03 0.561 0.03 0.561 0.09 0.309 0.09 0.309 0.102 ;
    END
  END Y
  PIN VDD
    DIRECTION INOUT ;
    USE POWER ;
    PORT
      LAYER M1 ;
        RECT -0.009 0.114 0.597 0.126 ;
    END
  END VDD
  PIN VSS
    DIRECTION INOUT ;
    USE GROUND ;
    PORT
      LAYER M1 ;
        RECT -0.009 -0.006 0.597 0.006 ;
    END
  END VSS
  OBS
    LAYER M1 ;
      POLYGON 0.279 0.102 0.279 0.066 0.531 0.066 0.531 0.054 0.279 0.054 0.279 0.018 0.057 0.018 0.057 0.03 0.267 0.03 0.267 0.09 0.057 0.09 0.057 0.102 ;
  END
  PROPERTY stopLevel 0 ;
  PROPERTY startLevel 0 ;
  PROPERTY snapMode "orthogonal" ;
  PROPERTY segSnapMode "orthogonal" ;
  PROPERTY pathCL "yes" ;
  PROPERTY lppVisibilityMode "donotCheckValidity" ;
  PROPERTY instanceDrawingMode "BBox" ;
  PROPERTY autoZoomScale 90 ;
  PROPERTY gridSpacing 1 ;
  PROPERTY xSnapSpacing 0.001 ;
  PROPERTY autoZoomMode "Pan" ;
  PROPERTY mergeScope "pcells" ;
  PROPERTY gridMultiple 5 ;
  PROPERTY arrayDisplay "Full" ;
  PROPERTY scrollPercent 25 ;
  PROPERTY displayResolution "Medium" ;
  PROPERTY instLabel "master" ;
  PROPERTY ySnapSpacing 0.001 ;
  PROPERTY filterSize 6 ;
  PROPERTY dimmingIntensity 50 ;
  PROPERTY filterSizeDrawingStyle "empty" ;
  PROPERTY dimmingScope "none" ;
END BUFx7

MACRO BUFx8
  CLASS CORE ;
  FOREIGN BUFx8 ;
  ORIGIN 0 0 ;
  SIZE 0.714 BY 0.144 ;
  SYMMETRY X Y ;
  SITE core ;
  PIN A
    DIRECTION INPUT ;
    USE SIGNAL ;
    PORT
      LAYER M1 ;
        POLYGON 0.027 0.102 0.027 0.066 0.321 0.066 0.321 0.054 0.027 0.054 0.027 0.018 0.015 0.018 0.015 0.102 ;
    END
  END A
  PIN Y
    DIRECTION OUTPUT ;
    USE SIGNAL ;
    PORT
      LAYER M1 ;
        POLYGON 0.699 0.102 0.699 0.018 0.393 0.018 0.393 0.03 0.687 0.03 0.687 0.09 0.393 0.09 0.393 0.102 ;
    END
  END Y
  PIN VDD
    DIRECTION INOUT ;
    USE POWER ;
    PORT
      LAYER M1 ;
        RECT -0.009 0.114 0.723 0.126 ;
    END
  END VDD
  PIN VSS
    DIRECTION INOUT ;
    USE GROUND ;
    PORT
      LAYER M1 ;
        RECT -0.009 -0.006 0.723 0.006 ;
    END
  END VSS
  OBS
    LAYER M1 ;
      POLYGON 0.363 0.102 0.363 0.066 0.657 0.066 0.657 0.054 0.363 0.054 0.363 0.018 0.057 0.018 0.057 0.03 0.351 0.03 0.351 0.09 0.057 0.09 0.057 0.102 ;
  END
  PROPERTY stopLevel 0 ;
  PROPERTY startLevel 0 ;
  PROPERTY snapMode "orthogonal" ;
  PROPERTY segSnapMode "orthogonal" ;
  PROPERTY pathCL "yes" ;
  PROPERTY lppVisibilityMode "donotCheckValidity" ;
  PROPERTY instanceDrawingMode "BBox" ;
  PROPERTY autoZoomScale 90 ;
  PROPERTY gridSpacing 1 ;
  PROPERTY xSnapSpacing 0.001 ;
  PROPERTY autoZoomMode "Pan" ;
  PROPERTY mergeScope "pcells" ;
  PROPERTY gridMultiple 5 ;
  PROPERTY arrayDisplay "Full" ;
  PROPERTY scrollPercent 25 ;
  PROPERTY displayResolution "Medium" ;
  PROPERTY instLabel "master" ;
  PROPERTY ySnapSpacing 0.001 ;
  PROPERTY filterSize 6 ;
  PROPERTY dimmingIntensity 50 ;
  PROPERTY filterSizeDrawingStyle "empty" ;
  PROPERTY dimmingScope "none" ;
END BUFx8

MACRO DFFHQNx1
  CLASS CORE ;
  FOREIGN DFFHQNx1 ;
  ORIGIN 0 0 ;
  SIZE 0.714 BY 0.144 ;
  SYMMETRY X Y ;
  SITE core ;
  PIN D
    DIRECTION INPUT ;
    USE SIGNAL ;
    PORT
      LAYER M1 ;
        RECT 0.141 0.018 0.153 0.102 ;
    END
  END D
  PIN CK
    DIRECTION INPUT ;
    USE SIGNAL ;
    PORT
      LAYER M1 ;
        RECT 0.043 0.018 0.055 0.102 ;
    END
  END CK
  PIN QN
    DIRECTION OUTPUT ;
    USE SIGNAL ;
    PORT
      LAYER M1 ;
        RECT 0.687 0.018 0.699 0.102 ;
    END
  END QN
  PIN VDD
    DIRECTION INOUT ;
    USE POWER ;
    PORT
      LAYER M1 ;
        RECT -0.009 0.114 0.723 0.126 ;
    END
  END VDD
  PIN VSS
    DIRECTION INOUT ;
    USE GROUND ;
    PORT
      LAYER M1 ;
        RECT -0.009 -0.006 0.723 0.006 ;
    END
  END VSS
  OBS
    LAYER M1 ;
      POLYGON 0.615 0.102 0.615 0.018 0.54 0.018 0.54 0.03 0.603 0.03 0.603 0.102 ;
      POLYGON 0.489 0.102 0.489 0.078 0.573 0.078 0.573 0.054 0.561 0.054 0.561 0.066 0.489 0.066 0.489 0.018 0.435 0.018 0.435 0.03 0.477 0.03 0.477 0.102 ;
      POLYGON 0.405 0.102 0.405 0.018 0.33 0.018 0.33 0.03 0.393 0.03 0.393 0.102 ;
      POLYGON 0.279 0.102 0.279 0.054 0.363 0.054 0.363 0.042 0.279 0.042 0.279 0.018 0.267 0.018 0.267 0.09 0.225 0.09 0.225 0.102 ;
      RECT 0.099 0.024 0.111 0.096 ;
      RECT 0.015 0.024 0.027 0.096 ;
      RECT 0.309 0.059 0.321 0.083 ;
      RECT 0.645 0.054 0.657 0.078 ;
      RECT 0.183 0.054 0.195 0.078 ;
      RECT 0.435 0.042 0.447 0.066 ;
      RECT 0.225 0.042 0.237 0.066 ;
      RECT 0.071 0.042 0.083 0.066 ;
    LAYER M2 ;
      RECT 0.561 0.066 0.657 0.078 ;
      RECT 0.099 0.066 0.321 0.078 ;
      RECT 0.015 0.042 0.447 0.054 ;
    LAYER V1 ;
      RECT 0.645 0.066 0.657 0.078 ;
      RECT 0.561 0.066 0.573 0.078 ;
      RECT 0.309 0.066 0.321 0.078 ;
      RECT 0.183 0.066 0.195 0.078 ;
      RECT 0.099 0.066 0.111 0.078 ;
      RECT 0.435 0.042 0.447 0.054 ;
      RECT 0.225 0.042 0.237 0.054 ;
      RECT 0.071 0.042 0.083 0.054 ;
      RECT 0.015 0.042 0.027 0.054 ;
  END
END DFFHQNx1

MACRO DFFHx1
  CLASS CORE ;
  FOREIGN DFFHx1 ;
  ORIGIN 0 0 ;
  SIZE 1.008 BY 0.144 ;
  SYMMETRY X Y ;
  SITE core ;
  PIN D
    DIRECTION INPUT ;
    USE SIGNAL ;
    PORT
      LAYER M1 ;
        RECT 0.141 0.018 0.153 0.102 ;
    END
  END D
  PIN CK
    DIRECTION INPUT ;
    USE SIGNAL ;
    PORT
      LAYER M1 ;
        RECT 0.043 0.018 0.055 0.102 ;
    END
  END CK
  PIN RESET
    DIRECTION INPUT ;
    USE SIGNAL ;
    PORT
      LAYER V1 ;
        RECT 0.498 0.09 0.51 0.102 ;
        RECT 0.624 0.09 0.636 0.102 ;
      LAYER M1 ;
        RECT 0.414 0.09 0.51 0.102 ;
        RECT 0.624 0.09 0.72 0.102 ;
      LAYER M2 ;
        RECT 0.498 0.09 0.636 0.102 ;
    END
  END RESET
  PIN SET
    DIRECTION INPUT ;
    USE SIGNAL ;
    PORT
      LAYER V1 ;
        RECT 0.498 0.018 0.51 0.03 ;
        RECT 0.624 0.018 0.636 0.03 ;
      LAYER M1 ;
        RECT 0.456 0.018 0.51 0.03 ;
        RECT 0.624 0.018 0.762 0.03 ;
      LAYER M2 ;
        RECT 0.498 0.018 0.636 0.03 ;
    END
  END SET
  PIN QN
    DIRECTION OUTPUT ;
    USE SIGNAL ;
    PORT
      LAYER M1 ;
        RECT 0.981 0.018 0.993 0.102 ;
    END
  END QN
  PIN VDD
    DIRECTION INOUT ;
    USE POWER ;
    PORT
      LAYER M1 ;
        RECT -0.009 0.114 1.017 0.126 ;
    END
  END VDD
  PIN VSS
    DIRECTION INOUT ;
    USE GROUND ;
    PORT
      LAYER M1 ;
        RECT -0.009 -0.006 1.017 0.006 ;
    END
  END VSS
  OBS
    LAYER M1 ;
      POLYGON 0.909 0.102 0.909 0.066 0.951 0.066 0.951 0.054 0.909 0.054 0.909 0.018 0.897 0.018 0.897 0.09 0.772 0.09 0.772 0.066 0.606 0.066 0.606 0.078 0.76 0.078 0.76 0.102 ;
      RECT 0.546 0.042 0.558 0.102 ;
      POLYGON 0.363 0.102 0.363 0.078 0.489 0.078 0.489 0.066 0.351 0.066 0.351 0.09 0.279 0.09 0.279 0.018 0.225 0.018 0.225 0.03 0.267 0.03 0.267 0.102 ;
      RECT 0.099 0.024 0.111 0.096 ;
      RECT 0.015 0.024 0.027 0.096 ;
      RECT 0.813 0.054 0.825 0.078 ;
      POLYGON 0.588 0.078 0.588 0.018 0.546 0.018 0.546 0.03 0.576 0.03 0.576 0.078 ;
      RECT 0.225 0.054 0.237 0.078 ;
      RECT 0.86 0.042 0.872 0.066 ;
      RECT 0.309 0.042 0.321 0.066 ;
      RECT 0.183 0.042 0.195 0.066 ;
      RECT 0.071 0.042 0.083 0.066 ;
      RECT 0.645 0.042 0.783 0.054 ;
      RECT 0.372 0.042 0.528 0.054 ;
      RECT 0.774 0.018 0.867 0.03 ;
      RECT 0.309 0.018 0.405 0.03 ;
    LAYER M2 ;
      RECT 0.099 0.066 0.825 0.078 ;
      RECT 0.015 0.042 0.872 0.054 ;
    LAYER V1 ;
      RECT 0.813 0.066 0.825 0.078 ;
      RECT 0.576 0.066 0.588 0.078 ;
      RECT 0.225 0.066 0.237 0.078 ;
      RECT 0.099 0.066 0.111 0.078 ;
      RECT 0.86 0.042 0.872 0.054 ;
      RECT 0.546 0.042 0.558 0.054 ;
      RECT 0.309 0.042 0.321 0.054 ;
      RECT 0.183 0.042 0.195 0.054 ;
      RECT 0.071 0.042 0.083 0.054 ;
      RECT 0.015 0.042 0.027 0.054 ;
  END
END DFFHx1

MACRO DHLx1
  CLASS CORE ;
  FOREIGN DHLx1 ;
  ORIGIN 0 0 ;
  SIZE 0.714 BY 0.144 ;
  SYMMETRY X Y ;
  SITE core ;
  PIN CK
    DIRECTION INPUT ;
    USE SIGNAL ;
    PORT
      LAYER M1 ;
        RECT 0.043 0.018 0.055 0.102 ;
    END
  END CK
  PIN D
    DIRECTION INPUT ;
    USE SIGNAL ;
    PORT
      LAYER M1 ;
        RECT 0.141 0.018 0.153 0.102 ;
    END
  END D
  PIN Q
    DIRECTION OUTPUT ;
    USE SIGNAL ;
    PORT
      LAYER M1 ;
        RECT 0.477 0.018 0.489 0.102 ;
    END
  END Q
  PIN VDD
    DIRECTION INOUT ;
    USE POWER ;
    PORT
      LAYER M1 ;
        RECT -0.009 0.114 0.723 0.126 ;
    END
  END VDD
  PIN VSS
    DIRECTION INOUT ;
    USE GROUND ;
    PORT
      LAYER M1 ;
        RECT -0.009 -0.006 0.723 0.006 ;
    END
  END VSS
  OBS
    LAYER M1 ;
      RECT 0.687 0.018 0.699 0.102 ;
      POLYGON 0.405 0.102 0.405 0.018 0.393 0.018 0.393 0.042 0.351 0.042 0.351 0.054 0.393 0.054 0.393 0.102 ;
      POLYGON 0.342 0.102 0.342 0.078 0.363 0.078 0.363 0.066 0.33 0.066 0.33 0.09 0.237 0.09 0.237 0.036 0.279 0.036 0.279 0.024 0.225 0.024 0.225 0.102 ;
      RECT 0.099 0.024 0.111 0.096 ;
      RECT 0.015 0.024 0.027 0.096 ;
      RECT 0.435 0.054 0.447 0.078 ;
      POLYGON 0.3 0.078 0.3 0.066 0.279 0.066 0.279 0.054 0.267 0.054 0.267 0.078 ;
      RECT 0.183 0.042 0.195 0.066 ;
      RECT 0.071 0.042 0.083 0.066 ;
      RECT 0.309 0.03 0.321 0.054 ;
    LAYER M2 ;
      RECT 0.33 0.066 0.447 0.078 ;
      RECT 0.099 0.066 0.279 0.078 ;
      RECT 0.015 0.042 0.321 0.054 ;
    LAYER V1 ;
      RECT 0.435 0.066 0.447 0.078 ;
      RECT 0.33 0.066 0.342 0.078 ;
      RECT 0.267 0.066 0.279 0.078 ;
      RECT 0.099 0.066 0.111 0.078 ;
      RECT 0.309 0.042 0.321 0.054 ;
      RECT 0.183 0.042 0.195 0.054 ;
      RECT 0.071 0.042 0.083 0.054 ;
      RECT 0.015 0.042 0.027 0.054 ;
  END
END DHLx1

MACRO INVx1
  CLASS CORE ;
  FOREIGN INVx1 ;
  ORIGIN 0 0 ;
  SIZE 0.084 BY 0.144 ;
  SYMMETRY X Y ;
  SITE core ;
  PIN A
    DIRECTION INPUT ;
    USE SIGNAL ;
    PORT
      LAYER M1 ;
        RECT 0.015 0.018 0.027 0.102 ;
    END
  END A
  PIN Y
    DIRECTION OUTPUT ;
    USE SIGNAL ;
    PORT
      LAYER M1 ;
        RECT 0.057 0.018 0.069 0.102 ;
    END
  END Y
  PIN VDD
    DIRECTION INOUT ;
    USE POWER ;
    PORT
      LAYER M1 ;
        RECT -0.009 0.114 0.093 0.126 ;
    END
  END VDD
  PIN VSS
    DIRECTION INOUT ;
    USE GROUND ;
    PORT
      LAYER M1 ;
        RECT -0.009 -0.006 0.093 0.006 ;
    END
  END VSS
END INVx1

MACRO INVx10
  CLASS CORE ;
  FOREIGN INVx10 ;
  ORIGIN 0 0 ;
  SIZE 0.462 BY 0.144 ;
  SYMMETRY X Y ;
  SITE core ;
  PIN A
    DIRECTION INPUT ;
    USE SIGNAL ;
    PORT
      LAYER M1 ;
        POLYGON 0.027 0.102 0.027 0.066 0.405 0.066 0.405 0.054 0.027 0.054 0.027 0.018 0.015 0.018 0.015 0.102 ;
    END
  END A
  PIN Y
    DIRECTION OUTPUT ;
    USE SIGNAL ;
    PORT
      LAYER M1 ;
        POLYGON 0.447 0.102 0.447 0.018 0.057 0.018 0.057 0.03 0.435 0.03 0.435 0.09 0.057 0.09 0.057 0.102 ;
    END
  END Y
  PIN VDD
    DIRECTION INOUT ;
    USE POWER ;
    PORT
      LAYER M1 ;
        RECT -0.009 0.114 0.471 0.126 ;
    END
  END VDD
  PIN VSS
    DIRECTION INOUT ;
    USE GROUND ;
    PORT
      LAYER M1 ;
        RECT -0.009 -0.006 0.471 0.006 ;
    END
  END VSS
END INVx10

MACRO INVx12
  CLASS CORE ;
  FOREIGN INVx12 ;
  ORIGIN 0 0 ;
  SIZE 0.546 BY 0.144 ;
  SYMMETRY X Y ;
  SITE core ;
  PIN A
    DIRECTION INPUT ;
    USE SIGNAL ;
    PORT
      LAYER M1 ;
        POLYGON 0.027 0.102 0.027 0.066 0.489 0.066 0.489 0.054 0.027 0.054 0.027 0.018 0.015 0.018 0.015 0.102 ;
    END
  END A
  PIN Y
    DIRECTION OUTPUT ;
    USE SIGNAL ;
    PORT
      LAYER M1 ;
        POLYGON 0.531 0.102 0.531 0.018 0.057 0.018 0.057 0.03 0.519 0.03 0.519 0.09 0.057 0.09 0.057 0.102 ;
    END
  END Y
  PIN VDD
    DIRECTION INOUT ;
    USE POWER ;
    PORT
      LAYER M1 ;
        RECT -0.009 0.114 0.555 0.126 ;
    END
  END VDD
  PIN VSS
    DIRECTION INOUT ;
    USE GROUND ;
    PORT
      LAYER M1 ;
        RECT -0.009 -0.006 0.555 0.006 ;
    END
  END VSS
END INVx12

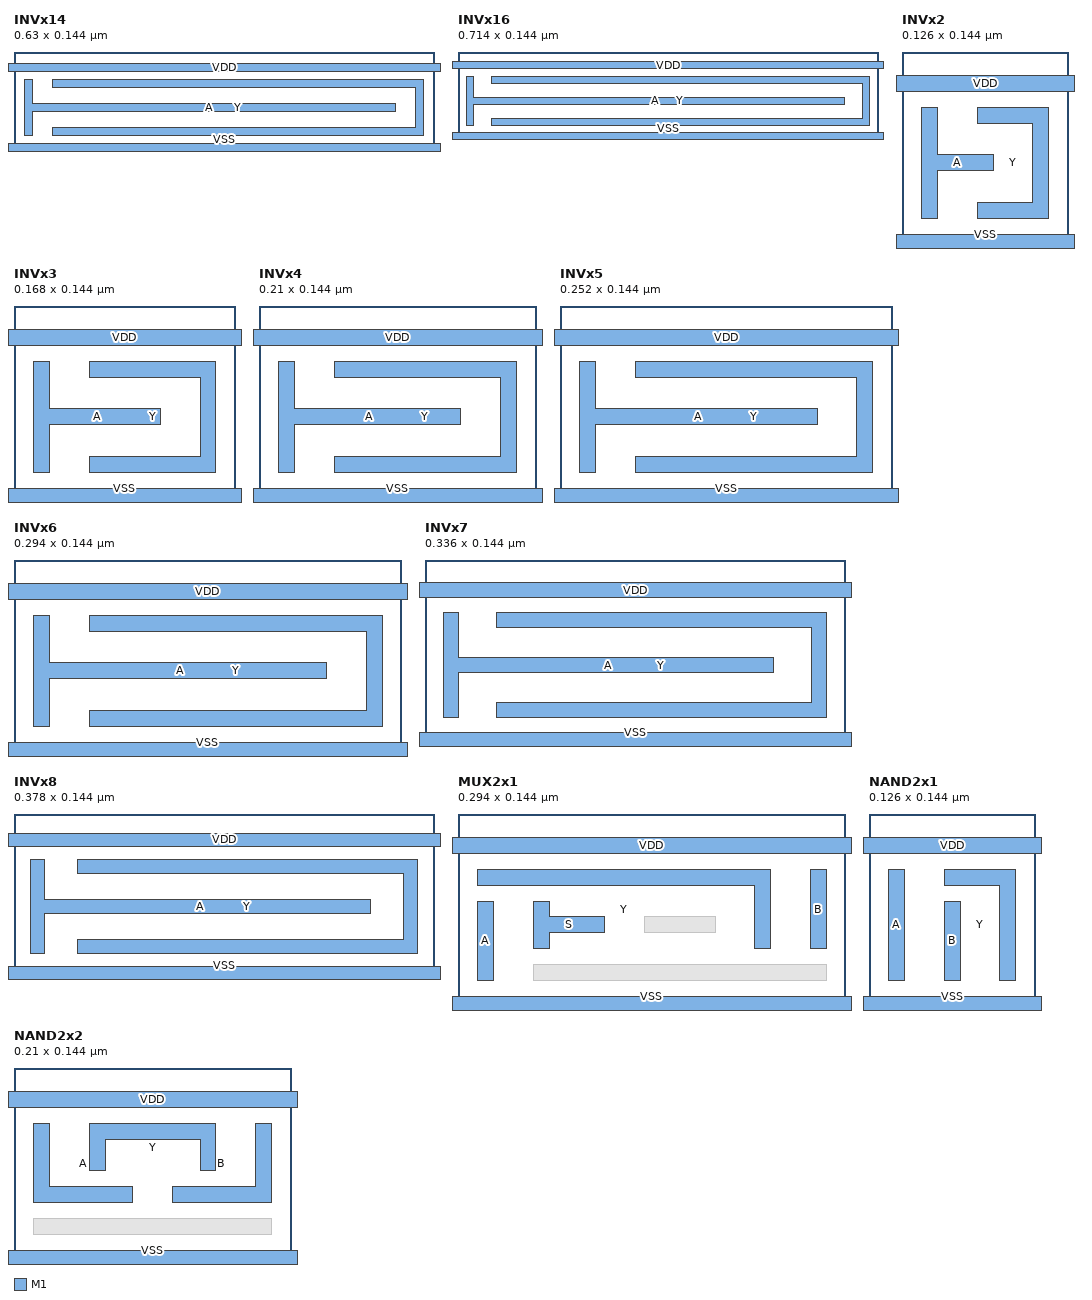
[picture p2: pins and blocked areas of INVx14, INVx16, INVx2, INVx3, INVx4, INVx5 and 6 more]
MACRO INVx14
  CLASS CORE ;
  FOREIGN INVx14 ;
  ORIGIN 0 0 ;
  SIZE 0.63 BY 0.144 ;
  SYMMETRY X Y ;
  SITE core ;
  PIN A
    DIRECTION INPUT ;
    USE SIGNAL ;
    PORT
      LAYER M1 ;
        POLYGON 0.027 0.102 0.027 0.066 0.573 0.066 0.573 0.054 0.027 0.054 0.027 0.018 0.015 0.018 0.015 0.102 ;
    END
  END A
  PIN Y
    DIRECTION OUTPUT ;
    USE SIGNAL ;
    PORT
      LAYER M1 ;
        POLYGON 0.615 0.102 0.615 0.018 0.057 0.018 0.057 0.03 0.603 0.03 0.603 0.09 0.057 0.09 0.057 0.102 ;
    END
  END Y
  PIN VDD
    DIRECTION INOUT ;
    USE POWER ;
    PORT
      LAYER M1 ;
        RECT -0.009 0.114 0.639 0.126 ;
    END
  END VDD
  PIN VSS
    DIRECTION INOUT ;
    USE GROUND ;
    PORT
      LAYER M1 ;
        RECT -0.009 -0.006 0.639 0.006 ;
    END
  END VSS
END INVx14

MACRO INVx16
  CLASS CORE ;
  FOREIGN INVx16 ;
  ORIGIN 0 0 ;
  SIZE 0.714 BY 0.144 ;
  SYMMETRY X Y ;
  SITE core ;
  PIN A
    DIRECTION INPUT ;
    USE SIGNAL ;
    PORT
      LAYER M1 ;
        POLYGON 0.027 0.102 0.027 0.066 0.657 0.066 0.657 0.054 0.027 0.054 0.027 0.018 0.015 0.018 0.015 0.102 ;
    END
  END A
  PIN Y
    DIRECTION OUTPUT ;
    USE SIGNAL ;
    PORT
      LAYER M1 ;
        POLYGON 0.699 0.102 0.699 0.018 0.057 0.018 0.057 0.03 0.687 0.03 0.687 0.09 0.057 0.09 0.057 0.102 ;
    END
  END Y
  PIN VDD
    DIRECTION INOUT ;
    USE POWER ;
    PORT
      LAYER M1 ;
        RECT -0.009 0.114 0.723 0.126 ;
    END
  END VDD
  PIN VSS
    DIRECTION INOUT ;
    USE GROUND ;
    PORT
      LAYER M1 ;
        RECT -0.009 -0.006 0.723 0.006 ;
    END
  END VSS
END INVx16

MACRO INVx2
  CLASS CORE ;
  FOREIGN INVx2 ;
  ORIGIN 0 0 ;
  SIZE 0.126 BY 0.144 ;
  SYMMETRY X Y ;
  SITE core ;
  PIN A
    DIRECTION INPUT ;
    USE SIGNAL ;
    PORT
      LAYER M1 ;
        POLYGON 0.027 0.102 0.027 0.066 0.069 0.066 0.069 0.054 0.027 0.054 0.027 0.018 0.015 0.018 0.015 0.102 ;
    END
  END A
  PIN Y
    DIRECTION OUTPUT ;
    USE SIGNAL ;
    PORT
      LAYER M1 ;
        POLYGON 0.111 0.102 0.111 0.018 0.057 0.018 0.057 0.03 0.099 0.03 0.099 0.09 0.057 0.09 0.057 0.102 ;
    END
  END Y
  PIN VDD
    DIRECTION INOUT ;
    USE POWER ;
    PORT
      LAYER M1 ;
        RECT -0.009 0.114 0.135 0.126 ;
    END
  END VDD
  PIN VSS
    DIRECTION INOUT ;
    USE GROUND ;
    PORT
      LAYER M1 ;
        RECT -0.009 -0.006 0.135 0.006 ;
    END
  END VSS
END INVx2

MACRO INVx3
  CLASS CORE ;
  FOREIGN INVx3 ;
  ORIGIN 0 0 ;
  SIZE 0.168 BY 0.144 ;
  SYMMETRY X Y ;
  SITE core ;
  PIN A
    DIRECTION INPUT ;
    USE SIGNAL ;
    PORT
      LAYER M1 ;
        POLYGON 0.027 0.102 0.027 0.066 0.111 0.066 0.111 0.054 0.027 0.054 0.027 0.018 0.015 0.018 0.015 0.102 ;
    END
  END A
  PIN Y
    DIRECTION OUTPUT ;
    USE SIGNAL ;
    PORT
      LAYER M1 ;
        POLYGON 0.153 0.102 0.153 0.018 0.057 0.018 0.057 0.03 0.141 0.03 0.141 0.09 0.057 0.09 0.057 0.102 ;
    END
  END Y
  PIN VDD
    DIRECTION INOUT ;
    USE POWER ;
    PORT
      LAYER M1 ;
        RECT -0.009 0.114 0.177 0.126 ;
    END
  END VDD
  PIN VSS
    DIRECTION INOUT ;
    USE GROUND ;
    PORT
      LAYER M1 ;
        RECT -0.009 -0.006 0.177 0.006 ;
    END
  END VSS
END INVx3

MACRO INVx4
  CLASS CORE ;
  FOREIGN INVx4 ;
  ORIGIN 0 0 ;
  SIZE 0.21 BY 0.144 ;
  SYMMETRY X Y ;
  SITE core ;
  PIN A
    DIRECTION INPUT ;
    USE SIGNAL ;
    PORT
      LAYER M1 ;
        POLYGON 0.027 0.102 0.027 0.066 0.153 0.066 0.153 0.054 0.027 0.054 0.027 0.018 0.015 0.018 0.015 0.102 ;
    END
  END A
  PIN Y
    DIRECTION OUTPUT ;
    USE SIGNAL ;
    PORT
      LAYER M1 ;
        POLYGON 0.195 0.102 0.195 0.018 0.057 0.018 0.057 0.03 0.183 0.03 0.183 0.09 0.057 0.09 0.057 0.102 ;
    END
  END Y
  PIN VDD
    DIRECTION INOUT ;
    USE POWER ;
    PORT
      LAYER M1 ;
        RECT -0.009 0.114 0.219 0.126 ;
    END
  END VDD
  PIN VSS
    DIRECTION INOUT ;
    USE GROUND ;
    PORT
      LAYER M1 ;
        RECT -0.009 -0.006 0.219 0.006 ;
    END
  END VSS
END INVx4

MACRO INVx5
  CLASS CORE ;
  FOREIGN INVx5 ;
  ORIGIN 0 0 ;
  SIZE 0.252 BY 0.144 ;
  SYMMETRY X Y ;
  SITE core ;
  PIN A
    DIRECTION INPUT ;
    USE SIGNAL ;
    PORT
      LAYER M1 ;
        POLYGON 0.027 0.102 0.027 0.066 0.195 0.066 0.195 0.054 0.027 0.054 0.027 0.018 0.015 0.018 0.015 0.102 ;
    END
  END A
  PIN Y
    DIRECTION OUTPUT ;
    USE SIGNAL ;
    PORT
      LAYER M1 ;
        POLYGON 0.237 0.102 0.237 0.018 0.057 0.018 0.057 0.03 0.225 0.03 0.225 0.09 0.057 0.09 0.057 0.102 ;
    END
  END Y
  PIN VDD
    DIRECTION INOUT ;
    USE POWER ;
    PORT
      LAYER M1 ;
        RECT -0.009 0.114 0.261 0.126 ;
    END
  END VDD
  PIN VSS
    DIRECTION INOUT ;
    USE GROUND ;
    PORT
      LAYER M1 ;
        RECT -0.009 -0.006 0.261 0.006 ;
    END
  END VSS
END INVx5

MACRO INVx6
  CLASS CORE ;
  FOREIGN INVx6 ;
  ORIGIN 0 0 ;
  SIZE 0.294 BY 0.144 ;
  SYMMETRY X Y ;
  SITE core ;
  PIN A
    DIRECTION INPUT ;
    USE SIGNAL ;
    PORT
      LAYER M1 ;
        POLYGON 0.027 0.102 0.027 0.066 0.237 0.066 0.237 0.054 0.027 0.054 0.027 0.018 0.015 0.018 0.015 0.102 ;
    END
  END A
  PIN Y
    DIRECTION OUTPUT ;
    USE SIGNAL ;
    PORT
      LAYER M1 ;
        POLYGON 0.279 0.102 0.279 0.018 0.057 0.018 0.057 0.03 0.267 0.03 0.267 0.09 0.057 0.09 0.057 0.102 ;
    END
  END Y
  PIN VDD
    DIRECTION INOUT ;
    USE POWER ;
    PORT
      LAYER M1 ;
        RECT -0.009 0.114 0.303 0.126 ;
    END
  END VDD
  PIN VSS
    DIRECTION INOUT ;
    USE GROUND ;
    PORT
      LAYER M1 ;
        RECT -0.009 -0.006 0.303 0.006 ;
    END
  END VSS
END INVx6

MACRO INVx7
  CLASS CORE ;
  FOREIGN INVx7 ;
  ORIGIN 0 0 ;
  SIZE 0.336 BY 0.144 ;
  SYMMETRY X Y ;
  SITE core ;
  PIN A
    DIRECTION INPUT ;
    USE SIGNAL ;
    PORT
      LAYER M1 ;
        POLYGON 0.027 0.102 0.027 0.066 0.279 0.066 0.279 0.054 0.027 0.054 0.027 0.018 0.015 0.018 0.015 0.102 ;
    END
  END A
  PIN Y
    DIRECTION OUTPUT ;
    USE SIGNAL ;
    PORT
      LAYER M1 ;
        POLYGON 0.321 0.102 0.321 0.018 0.057 0.018 0.057 0.03 0.309 0.03 0.309 0.09 0.057 0.09 0.057 0.102 ;
    END
  END Y
  PIN VDD
    DIRECTION INOUT ;
    USE POWER ;
    PORT
      LAYER M1 ;
        RECT -0.009 0.114 0.345 0.126 ;
    END
  END VDD
  PIN VSS
    DIRECTION INOUT ;
    USE GROUND ;
    PORT
      LAYER M1 ;
        RECT -0.009 -0.006 0.345 0.006 ;
    END
  END VSS
END INVx7

MACRO INVx8
  CLASS CORE ;
  FOREIGN INVx8 ;
  ORIGIN 0 0 ;
  SIZE 0.378 BY 0.144 ;
  SYMMETRY X Y ;
  SITE core ;
  PIN A
    DIRECTION INPUT ;
    USE SIGNAL ;
    PORT
      LAYER M1 ;
        POLYGON 0.027 0.102 0.027 0.066 0.321 0.066 0.321 0.054 0.027 0.054 0.027 0.018 0.015 0.018 0.015 0.102 ;
    END
  END A
  PIN Y
    DIRECTION OUTPUT ;
    USE SIGNAL ;
    PORT
      LAYER M1 ;
        POLYGON 0.363 0.102 0.363 0.018 0.057 0.018 0.057 0.03 0.351 0.03 0.351 0.09 0.057 0.09 0.057 0.102 ;
    END
  END Y
  PIN VDD
    DIRECTION INOUT ;
    USE POWER ;
    PORT
      LAYER M1 ;
        RECT -0.009 0.114 0.387 0.126 ;
    END
  END VDD
  PIN VSS
    DIRECTION INOUT ;
    USE GROUND ;
    PORT
      LAYER M1 ;
        RECT -0.009 -0.006 0.387 0.006 ;
    END
  END VSS
END INVx8

MACRO MUX2x1
  CLASS CORE ;
  FOREIGN MUX2x1 ;
  ORIGIN 0 0 ;
  SIZE 0.294 BY 0.144 ;
  SYMMETRY X Y ;
  SITE core ;
  PIN A
    DIRECTION INPUT ;
    USE SIGNAL ;
    PORT
      LAYER M1 ;
        RECT 0.015 0.018 0.027 0.078 ;
    END
  END A
  PIN B
    DIRECTION INPUT ;
    USE SIGNAL ;
    PORT
      LAYER M1 ;
        RECT 0.267 0.042 0.279 0.102 ;
    END
  END B
  PIN S
    DIRECTION INPUT ;
    USE SIGNAL ;
    PORT
      LAYER M1 ;
        POLYGON 0.069 0.078 0.069 0.066 0.111 0.066 0.111 0.054 0.069 0.054 0.069 0.042 0.057 0.042 0.057 0.078 ;
    END
  END S
  PIN Y
    DIRECTION OUTPUT ;
    USE SIGNAL ;
    PORT
      LAYER M1 ;
        POLYGON 0.237 0.102 0.237 0.042 0.225 0.042 0.225 0.09 0.015 0.09 0.015 0.102 ;
    END
  END Y
  PIN VDD
    DIRECTION INOUT ;
    USE POWER ;
    PORT
      LAYER M1 ;
        RECT -0.009 0.114 0.303 0.126 ;
    END
  END VDD
  PIN VSS
    DIRECTION INOUT ;
    USE GROUND ;
    PORT
      LAYER M1 ;
        RECT -0.009 -0.006 0.303 0.006 ;
    END
  END VSS
  OBS
    LAYER M1 ;
      RECT 0.141 0.054 0.195 0.066 ;
      RECT 0.057 0.018 0.279 0.03 ;
  END
END MUX2x1

MACRO NAND2x1
  CLASS CORE ;
  FOREIGN NAND2x1 ;
  ORIGIN 0 0 ;
  SIZE 0.126 BY 0.144 ;
  SYMMETRY X Y ;
  SITE core ;
  PIN A
    DIRECTION INPUT ;
    USE SIGNAL ;
    PORT
      LAYER M1 ;
        RECT 0.015 0.018 0.027 0.102 ;
    END
  END A
  PIN B
    DIRECTION INPUT ;
    USE SIGNAL ;
    PORT
      LAYER M1 ;
        RECT 0.057 0.018 0.069 0.078 ;
    END
  END B
  PIN Y
    DIRECTION OUTPUT ;
    USE SIGNAL ;
    PORT
      LAYER M1 ;
        POLYGON 0.111 0.102 0.111 0.018 0.099 0.018 0.099 0.09 0.057 0.09 0.057 0.102 ;
    END
  END Y
  PIN VDD
    DIRECTION INOUT ;
    USE POWER ;
    PORT
      LAYER M1 ;
        RECT -0.009 0.114 0.135 0.126 ;
    END
  END VDD
  PIN VSS
    DIRECTION INOUT ;
    USE GROUND ;
    PORT
      LAYER M1 ;
        RECT -0.009 -0.006 0.135 0.006 ;
    END
  END VSS
END NAND2x1

MACRO NAND2x2
  CLASS CORE ;
  FOREIGN NAND2x2 ;
  ORIGIN 0 0 ;
  SIZE 0.21 BY 0.144 ;
  SYMMETRY X Y ;
  SITE core ;
  PIN A
    DIRECTION INPUT ;
    USE SIGNAL ;
    PORT
      LAYER M1 ;
        POLYGON 0.027 0.102 0.027 0.054 0.09 0.054 0.09 0.042 0.015 0.042 0.015 0.102 ;
    END
  END A
  PIN B
    DIRECTION INPUT ;
    USE SIGNAL ;
    PORT
      LAYER M1 ;
        POLYGON 0.195 0.102 0.195 0.042 0.12 0.042 0.12 0.054 0.183 0.054 0.183 0.102 ;
    END
  END B
  PIN Y
    DIRECTION OUTPUT ;
    USE SIGNAL ;
    PORT
      LAYER M1 ;
        POLYGON 0.153 0.102 0.153 0.066 0.141 0.066 0.141 0.09 0.069 0.09 0.069 0.066 0.057 0.066 0.057 0.102 ;
    END
  END Y
  PIN VDD
    DIRECTION INOUT ;
    USE POWER ;
    PORT
      LAYER M1 ;
        RECT -0.009 0.114 0.219 0.126 ;
    END
  END VDD
  PIN VSS
    DIRECTION INOUT ;
    USE GROUND ;
    PORT
      LAYER M1 ;
        RECT -0.009 -0.006 0.219 0.006 ;
    END
  END VSS
  OBS
    LAYER M1 ;
      RECT 0.015 0.018 0.195 0.03 ;
  END
END NAND2x2

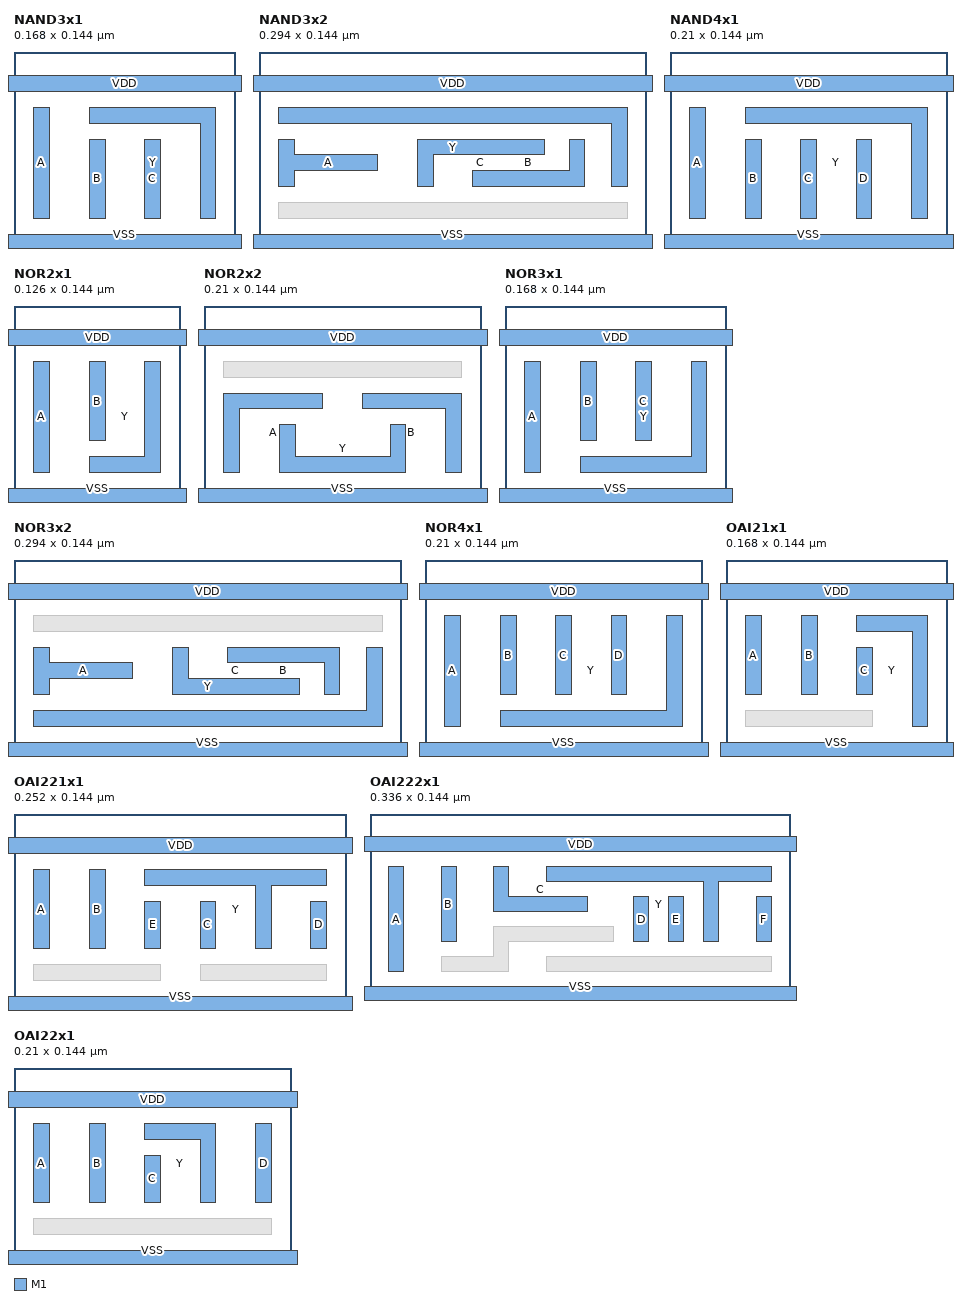
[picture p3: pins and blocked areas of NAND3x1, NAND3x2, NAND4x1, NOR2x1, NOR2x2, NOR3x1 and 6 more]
MACRO NAND3x1
  CLASS CORE ;
  FOREIGN NAND3x1 ;
  ORIGIN 0 0 ;
  SIZE 0.168 BY 0.144 ;
  SYMMETRY X Y ;
  SITE core ;
  PIN A
    DIRECTION INPUT ;
    USE SIGNAL ;
    PORT
      LAYER M1 ;
        RECT 0.015 0.018 0.027 0.102 ;
    END
  END A
  PIN B
    DIRECTION INPUT ;
    USE SIGNAL ;
    PORT
      LAYER M1 ;
        RECT 0.057 0.018 0.069 0.078 ;
    END
  END B
  PIN C
    DIRECTION INPUT ;
    USE SIGNAL ;
    PORT
      LAYER M1 ;
        RECT 0.099 0.018 0.111 0.078 ;
    END
  END C
  PIN Y
    DIRECTION OUTPUT ;
    USE SIGNAL ;
    PORT
      LAYER M1 ;
        POLYGON 0.153 0.102 0.153 0.018 0.141 0.018 0.141 0.09 0.057 0.09 0.057 0.102 ;
    END
  END Y
  PIN VDD
    DIRECTION INOUT ;
    USE POWER ;
    PORT
      LAYER M1 ;
        RECT -0.009 0.114 0.177 0.126 ;
    END
  END VDD
  PIN VSS
    DIRECTION INOUT ;
    USE GROUND ;
    PORT
      LAYER M1 ;
        RECT -0.009 -0.006 0.177 0.006 ;
    END
  END VSS
END NAND3x1

MACRO NAND3x2
  CLASS CORE ;
  FOREIGN NAND3x2 ;
  ORIGIN 0 0 ;
  SIZE 0.294 BY 0.144 ;
  SYMMETRY X Y ;
  SITE core ;
  PIN A
    DIRECTION INPUT ;
    USE SIGNAL ;
    PORT
      LAYER M1 ;
        POLYGON 0.027 0.078 0.027 0.066 0.09 0.066 0.09 0.054 0.027 0.054 0.027 0.042 0.015 0.042 0.015 0.078 ;
    END
  END A
  PIN B
    DIRECTION INPUT ;
    USE SIGNAL ;
    PORT
      LAYER M1 ;
        POLYGON 0.247 0.078 0.247 0.042 0.162 0.042 0.162 0.054 0.235 0.054 0.235 0.078 ;
    END
  END B
  PIN C
    DIRECTION INPUT ;
    USE SIGNAL ;
    PORT
      LAYER M1 ;
        POLYGON 0.216 0.078 0.216 0.066 0.132 0.066 0.132 0.042 0.12 0.042 0.12 0.078 ;
    END
  END C
  PIN Y
    DIRECTION OUTPUT ;
    USE SIGNAL ;
    PORT
      LAYER M1 ;
        POLYGON 0.279 0.102 0.279 0.042 0.267 0.042 0.267 0.09 0.015 0.09 0.015 0.102 ;
    END
  END Y
  PIN VDD
    DIRECTION INOUT ;
    USE POWER ;
    PORT
      LAYER M1 ;
        RECT -0.009 0.114 0.303 0.126 ;
    END
  END VDD
  PIN VSS
    DIRECTION INOUT ;
    USE GROUND ;
    PORT
      LAYER M1 ;
        RECT -0.009 -0.006 0.303 0.006 ;
    END
  END VSS
  OBS
    LAYER M1 ;
      RECT 0.015 0.018 0.279 0.03 ;
  END
END NAND3x2

MACRO NAND4x1
  CLASS CORE ;
  FOREIGN NAND4x1 ;
  ORIGIN 0 0 ;
  SIZE 0.21 BY 0.144 ;
  SYMMETRY X Y ;
  SITE core ;
  PIN A
    DIRECTION INPUT ;
    USE SIGNAL ;
    PORT
      LAYER M1 ;
        RECT 0.015 0.018 0.027 0.102 ;
    END
  END A
  PIN B
    DIRECTION INPUT ;
    USE SIGNAL ;
    PORT
      LAYER M1 ;
        RECT 0.057 0.018 0.069 0.078 ;
    END
  END B
  PIN C
    DIRECTION INPUT ;
    USE SIGNAL ;
    PORT
      LAYER M1 ;
        RECT 0.099 0.018 0.111 0.078 ;
    END
  END C
  PIN D
    DIRECTION INPUT ;
    USE SIGNAL ;
    PORT
      LAYER M1 ;
        RECT 0.141 0.018 0.153 0.078 ;
    END
  END D
  PIN Y
    DIRECTION OUTPUT ;
    USE SIGNAL ;
    PORT
      LAYER M1 ;
        POLYGON 0.195 0.102 0.195 0.018 0.183 0.018 0.183 0.09 0.057 0.09 0.057 0.102 ;
    END
  END Y
  PIN VDD
    DIRECTION INOUT ;
    USE POWER ;
    PORT
      LAYER M1 ;
        RECT -0.009 0.114 0.219 0.126 ;
    END
  END VDD
  PIN VSS
    DIRECTION INOUT ;
    USE GROUND ;
    PORT
      LAYER M1 ;
        RECT -0.009 -0.006 0.219 0.006 ;
    END
  END VSS
END NAND4x1

MACRO NOR2x1
  CLASS CORE ;
  FOREIGN NOR2x1 ;
  ORIGIN 0 0 ;
  SIZE 0.126 BY 0.144 ;
  SYMMETRY X Y ;
  SITE core ;
  PIN A
    DIRECTION INPUT ;
    USE SIGNAL ;
    PORT
      LAYER M1 ;
        RECT 0.015 0.018 0.027 0.102 ;
    END
  END A
  PIN B
    DIRECTION INPUT ;
    USE SIGNAL ;
    PORT
      LAYER M1 ;
        RECT 0.057 0.042 0.069 0.102 ;
    END
  END B
  PIN Y
    DIRECTION OUTPUT ;
    USE SIGNAL ;
    PORT
      LAYER M1 ;
        POLYGON 0.111 0.102 0.111 0.018 0.057 0.018 0.057 0.03 0.099 0.03 0.099 0.102 ;
    END
  END Y
  PIN VDD
    DIRECTION INOUT ;
    USE POWER ;
    PORT
      LAYER M1 ;
        RECT -0.009 0.114 0.135 0.126 ;
    END
  END VDD
  PIN VSS
    DIRECTION INOUT ;
    USE GROUND ;
    PORT
      LAYER M1 ;
        RECT -0.009 -0.006 0.135 0.006 ;
    END
  END VSS
END NOR2x1

MACRO NOR2x2
  CLASS CORE ;
  FOREIGN NOR2x2 ;
  ORIGIN 0 0 ;
  SIZE 0.21 BY 0.144 ;
  SYMMETRY X Y ;
  SITE core ;
  PIN A
    DIRECTION INPUT ;
    USE SIGNAL ;
    PORT
      LAYER M1 ;
        POLYGON 0.09 0.078 0.09 0.066 0.027 0.066 0.027 0.018 0.015 0.018 0.015 0.078 ;
    END
  END A
  PIN B
    DIRECTION INPUT ;
    USE SIGNAL ;
    PORT
      LAYER M1 ;
        POLYGON 0.195 0.078 0.195 0.018 0.183 0.018 0.183 0.066 0.12 0.066 0.12 0.078 ;
    END
  END B
  PIN Y
    DIRECTION OUTPUT ;
    USE SIGNAL ;
    PORT
      LAYER M1 ;
        POLYGON 0.153 0.054 0.153 0.018 0.057 0.018 0.057 0.054 0.069 0.054 0.069 0.03 0.141 0.03 0.141 0.054 ;
    END
  END Y
  PIN VDD
    DIRECTION INOUT ;
    USE POWER ;
    PORT
      LAYER M1 ;
        RECT -0.009 0.114 0.219 0.126 ;
    END
  END VDD
  PIN VSS
    DIRECTION INOUT ;
    USE GROUND ;
    PORT
      LAYER M1 ;
        RECT -0.009 -0.006 0.219 0.006 ;
    END
  END VSS
  OBS
    LAYER M1 ;
      RECT 0.015 0.09 0.195 0.102 ;
  END
END NOR2x2

MACRO NOR3x1
  CLASS CORE ;
  FOREIGN NOR3x1 ;
  ORIGIN 0 0 ;
  SIZE 0.168 BY 0.144 ;
  SYMMETRY X Y ;
  SITE core ;
  PIN A
    DIRECTION INPUT ;
    USE SIGNAL ;
    PORT
      LAYER M1 ;
        RECT 0.015 0.018 0.027 0.102 ;
    END
  END A
  PIN B
    DIRECTION INPUT ;
    USE SIGNAL ;
    PORT
      LAYER M1 ;
        RECT 0.057 0.042 0.069 0.102 ;
    END
  END B
  PIN C
    DIRECTION INPUT ;
    USE SIGNAL ;
    PORT
      LAYER M1 ;
        RECT 0.099 0.042 0.111 0.102 ;
    END
  END C
  PIN Y
    DIRECTION OUTPUT ;
    USE SIGNAL ;
    PORT
      LAYER M1 ;
        POLYGON 0.153 0.102 0.153 0.018 0.057 0.018 0.057 0.03 0.141 0.03 0.141 0.102 ;
    END
  END Y
  PIN VDD
    DIRECTION INOUT ;
    USE POWER ;
    PORT
      LAYER M1 ;
        RECT -0.009 0.114 0.177 0.126 ;
    END
  END VDD
  PIN VSS
    DIRECTION INOUT ;
    USE GROUND ;
    PORT
      LAYER M1 ;
        RECT -0.009 -0.006 0.177 0.006 ;
    END
  END VSS
END NOR3x1

MACRO NOR3x2
  CLASS CORE ;
  FOREIGN NOR3x2 ;
  ORIGIN 0 0 ;
  SIZE 0.294 BY 0.144 ;
  SYMMETRY X Y ;
  SITE core ;
  PIN A
    DIRECTION INPUT ;
    USE SIGNAL ;
    PORT
      LAYER M1 ;
        POLYGON 0.027 0.078 0.027 0.066 0.09 0.066 0.09 0.054 0.027 0.054 0.027 0.042 0.015 0.042 0.015 0.078 ;
    END
  END A
  PIN B
    DIRECTION INPUT ;
    USE SIGNAL ;
    PORT
      LAYER M1 ;
        POLYGON 0.247 0.078 0.247 0.042 0.235 0.042 0.235 0.066 0.162 0.066 0.162 0.078 ;
    END
  END B
  PIN C
    DIRECTION INPUT ;
    USE SIGNAL ;
    PORT
      LAYER M1 ;
        POLYGON 0.132 0.078 0.132 0.054 0.216 0.054 0.216 0.042 0.12 0.042 0.12 0.078 ;
    END
  END C
  PIN Y
    DIRECTION OUTPUT ;
    USE SIGNAL ;
    PORT
      LAYER M1 ;
        POLYGON 0.279 0.078 0.279 0.018 0.015 0.018 0.015 0.03 0.267 0.03 0.267 0.078 ;
    END
  END Y
  PIN VDD
    DIRECTION INOUT ;
    USE POWER ;
    PORT
      LAYER M1 ;
        RECT -0.009 0.114 0.303 0.126 ;
    END
  END VDD
  PIN VSS
    DIRECTION INOUT ;
    USE GROUND ;
    PORT
      LAYER M1 ;
        RECT -0.009 -0.006 0.303 0.006 ;
    END
  END VSS
  OBS
    LAYER M1 ;
      RECT 0.015 0.09 0.279 0.102 ;
  END
END NOR3x2

MACRO NOR4x1
  CLASS CORE ;
  FOREIGN NOR4x1 ;
  ORIGIN 0 0 ;
  SIZE 0.21 BY 0.144 ;
  SYMMETRY X Y ;
  SITE core ;
  PIN A
    DIRECTION INPUT ;
    USE SIGNAL ;
    PORT
      LAYER M1 ;
        RECT 0.015 0.018 0.027 0.102 ;
    END
  END A
  PIN B
    DIRECTION INPUT ;
    USE SIGNAL ;
    PORT
      LAYER M1 ;
        RECT 0.057 0.042 0.069 0.102 ;
    END
  END B
  PIN C
    DIRECTION INPUT ;
    USE SIGNAL ;
    PORT
      LAYER M1 ;
        RECT 0.099 0.042 0.111 0.102 ;
    END
  END C
  PIN D
    DIRECTION INPUT ;
    USE SIGNAL ;
    PORT
      LAYER M1 ;
        RECT 0.141 0.042 0.153 0.102 ;
    END
  END D
  PIN Y
    DIRECTION OUTPUT ;
    USE SIGNAL ;
    PORT
      LAYER M1 ;
        POLYGON 0.195 0.102 0.195 0.018 0.057 0.018 0.057 0.03 0.183 0.03 0.183 0.102 ;
    END
  END Y
  PIN VDD
    DIRECTION INOUT ;
    USE POWER ;
    PORT
      LAYER M1 ;
        RECT -0.009 0.114 0.219 0.126 ;
    END
  END VDD
  PIN VSS
    DIRECTION INOUT ;
    USE GROUND ;
    PORT
      LAYER M1 ;
        RECT -0.009 -0.006 0.219 0.006 ;
    END
  END VSS
END NOR4x1

MACRO OAI21x1
  CLASS CORE ;
  FOREIGN OAI21x1 ;
  ORIGIN 0 0 ;
  SIZE 0.168 BY 0.144 ;
  SYMMETRY X Y ;
  SITE core ;
  PIN A
    DIRECTION INPUT ;
    USE SIGNAL ;
    PORT
      LAYER M1 ;
        RECT 0.015 0.042 0.027 0.102 ;
    END
  END A
  PIN B
    DIRECTION INPUT ;
    USE SIGNAL ;
    PORT
      LAYER M1 ;
        RECT 0.057 0.042 0.069 0.102 ;
    END
  END B
  PIN C
    DIRECTION INPUT ;
    USE SIGNAL ;
    PORT
      LAYER M1 ;
        RECT 0.099 0.042 0.111 0.078 ;
    END
  END C
  PIN Y
    DIRECTION OUTPUT ;
    USE SIGNAL ;
    PORT
      LAYER M1 ;
        POLYGON 0.153 0.102 0.153 0.018 0.141 0.018 0.141 0.09 0.099 0.09 0.099 0.102 ;
    END
  END Y
  PIN VDD
    DIRECTION INOUT ;
    USE POWER ;
    PORT
      LAYER M1 ;
        RECT -0.009 0.114 0.177 0.126 ;
    END
  END VDD
  PIN VSS
    DIRECTION INOUT ;
    USE GROUND ;
    PORT
      LAYER M1 ;
        RECT -0.009 -0.006 0.177 0.006 ;
    END
  END VSS
  OBS
    LAYER M1 ;
      RECT 0.015 0.018 0.111 0.03 ;
  END
END OAI21x1

MACRO OAI221x1
  CLASS CORE ;
  FOREIGN OAI221x1 ;
  ORIGIN 0 0 ;
  SIZE 0.252 BY 0.144 ;
  SYMMETRY X Y ;
  SITE core ;
  PIN A
    DIRECTION INPUT ;
    USE SIGNAL ;
    PORT
      LAYER M1 ;
        RECT 0.015 0.042 0.027 0.102 ;
    END
  END A
  PIN B
    DIRECTION INPUT ;
    USE SIGNAL ;
    PORT
      LAYER M1 ;
        RECT 0.057 0.042 0.069 0.102 ;
    END
  END B
  PIN C
    DIRECTION INPUT ;
    USE SIGNAL ;
    PORT
      LAYER M1 ;
        RECT 0.141 0.042 0.153 0.078 ;
    END
  END C
  PIN D
    DIRECTION INPUT ;
    USE SIGNAL ;
    PORT
      LAYER M1 ;
        RECT 0.225 0.042 0.237 0.078 ;
    END
  END D
  PIN E
    DIRECTION INPUT ;
    USE SIGNAL ;
    PORT
      LAYER M1 ;
        RECT 0.099 0.042 0.111 0.078 ;
    END
  END E
  PIN Y
    DIRECTION OUTPUT ;
    USE SIGNAL ;
    PORT
      LAYER M1 ;
        POLYGON 0.237 0.102 0.237 0.09 0.195 0.09 0.195 0.042 0.183 0.042 0.183 0.09 0.099 0.09 0.099 0.102 ;
    END
  END Y
  PIN VDD
    DIRECTION INOUT ;
    USE POWER ;
    PORT
      LAYER M1 ;
        RECT -0.009 0.114 0.261 0.126 ;
    END
  END VDD
  PIN VSS
    DIRECTION INOUT ;
    USE GROUND ;
    PORT
      LAYER M1 ;
        RECT -0.009 -0.006 0.261 0.006 ;
    END
  END VSS
  OBS
    LAYER M1 ;
      RECT 0.141 0.018 0.237 0.03 ;
      RECT 0.015 0.018 0.111 0.03 ;
  END
END OAI221x1

MACRO OAI222x1
  CLASS CORE ;
  FOREIGN OAI222x1 ;
  ORIGIN 0 0 ;
  SIZE 0.336 BY 0.144 ;
  SYMMETRY X Y ;
  SITE core ;
  PIN A
    DIRECTION INPUT ;
    USE SIGNAL ;
    PORT
      LAYER M1 ;
        RECT 0.015 0.018 0.027 0.102 ;
    END
  END A
  PIN B
    DIRECTION INPUT ;
    USE SIGNAL ;
    PORT
      LAYER M1 ;
        RECT 0.057 0.042 0.069 0.102 ;
    END
  END B
  PIN C
    DIRECTION INPUT ;
    USE SIGNAL ;
    PORT
      LAYER M1 ;
        POLYGON 0.111 0.102 0.111 0.078 0.174 0.078 0.174 0.066 0.099 0.066 0.099 0.102 ;
    END
  END C
  PIN D
    DIRECTION INPUT ;
    USE SIGNAL ;
    PORT
      LAYER M1 ;
        RECT 0.211 0.042 0.223 0.078 ;
    END
  END D
  PIN E
    DIRECTION INPUT ;
    USE SIGNAL ;
    PORT
      LAYER M1 ;
        RECT 0.239 0.042 0.251 0.078 ;
    END
  END E
  PIN F
    DIRECTION INPUT ;
    USE SIGNAL ;
    PORT
      LAYER M1 ;
        RECT 0.309 0.042 0.321 0.078 ;
    END
  END F
  PIN Y
    DIRECTION OUTPUT ;
    USE SIGNAL ;
    PORT
      LAYER M1 ;
        POLYGON 0.321 0.102 0.321 0.09 0.279 0.09 0.279 0.042 0.267 0.042 0.267 0.09 0.141 0.09 0.141 0.102 ;
    END
  END Y
  PIN VDD
    DIRECTION INOUT ;
    USE POWER ;
    PORT
      LAYER M1 ;
        RECT -0.009 0.114 0.345 0.126 ;
    END
  END VDD
  PIN VSS
    DIRECTION INOUT ;
    USE GROUND ;
    PORT
      LAYER M1 ;
        RECT -0.009 -0.006 0.345 0.006 ;
    END
  END VSS
  OBS
    LAYER M1 ;
      POLYGON 0.195 0.054 0.195 0.042 0.111 0.042 0.111 0.018 0.057 0.018 0.057 0.03 0.099 0.03 0.099 0.054 ;
      RECT 0.141 0.018 0.321 0.03 ;
  END
END OAI222x1

MACRO OAI22x1
  CLASS CORE ;
  FOREIGN OAI22x1 ;
  ORIGIN 0 0 ;
  SIZE 0.21 BY 0.144 ;
  SYMMETRY X Y ;
  SITE core ;
  PIN A
    DIRECTION INPUT ;
    USE SIGNAL ;
    PORT
      LAYER M1 ;
        RECT 0.015 0.042 0.027 0.102 ;
    END
  END A
  PIN B
    DIRECTION INPUT ;
    USE SIGNAL ;
    PORT
      LAYER M1 ;
        RECT 0.057 0.042 0.069 0.102 ;
    END
  END B
  PIN C
    DIRECTION INPUT ;
    USE SIGNAL ;
    PORT
      LAYER M1 ;
        RECT 0.099 0.042 0.111 0.078 ;
    END
  END C
  PIN D
    DIRECTION INPUT ;
    USE SIGNAL ;
    PORT
      LAYER M1 ;
        RECT 0.183 0.042 0.195 0.102 ;
    END
  END D
  PIN Y
    DIRECTION OUTPUT ;
    USE SIGNAL ;
    PORT
      LAYER M1 ;
        POLYGON 0.153 0.102 0.153 0.042 0.141 0.042 0.141 0.09 0.099 0.09 0.099 0.102 ;
    END
  END Y
  PIN VDD
    DIRECTION INOUT ;
    USE POWER ;
    PORT
      LAYER M1 ;
        RECT -0.009 0.114 0.219 0.126 ;
    END
  END VDD
  PIN VSS
    DIRECTION INOUT ;
    USE GROUND ;
    PORT
      LAYER M1 ;
        RECT -0.009 -0.006 0.219 0.006 ;
    END
  END VSS
  OBS
    LAYER M1 ;
      RECT 0.015 0.018 0.195 0.03 ;
  END
END OAI22x1

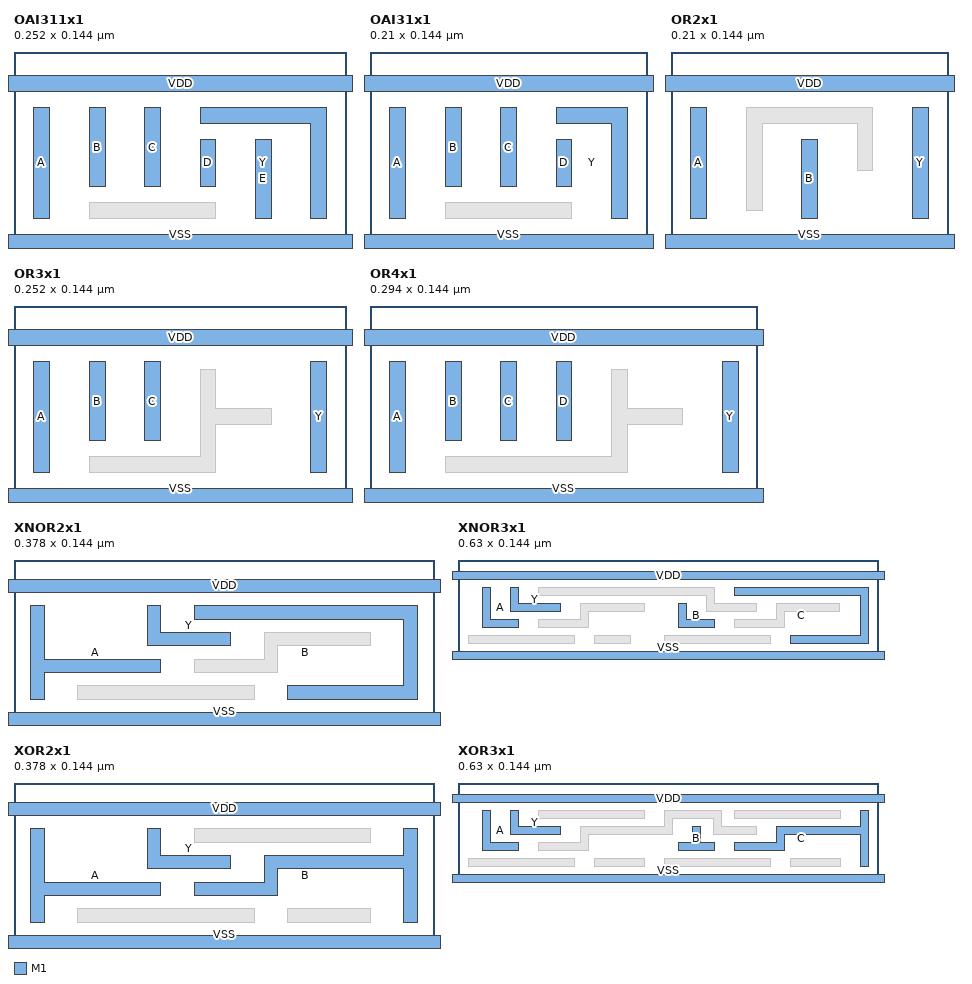
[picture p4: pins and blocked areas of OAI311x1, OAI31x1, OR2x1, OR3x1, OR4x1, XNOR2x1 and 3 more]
MACRO OAI311x1
  CLASS CORE ;
  FOREIGN OAI311x1 ;
  ORIGIN 0 0 ;
  SIZE 0.252 BY 0.144 ;
  SYMMETRY X Y ;
  SITE core ;
  PIN A
    DIRECTION INPUT ;
    USE SIGNAL ;
    PORT
      LAYER M1 ;
        RECT 0.015 0.018 0.027 0.102 ;
    END
  END A
  PIN B
    DIRECTION INPUT ;
    USE SIGNAL ;
    PORT
      LAYER M1 ;
        RECT 0.057 0.042 0.069 0.102 ;
    END
  END B
  PIN C
    DIRECTION INPUT ;
    USE SIGNAL ;
    PORT
      LAYER M1 ;
        RECT 0.099 0.042 0.111 0.102 ;
    END
  END C
  PIN D
    DIRECTION INPUT ;
    USE SIGNAL ;
    PORT
      LAYER M1 ;
        RECT 0.141 0.042 0.153 0.078 ;
    END
  END D
  PIN E
    DIRECTION INPUT ;
    USE SIGNAL ;
    PORT
      LAYER M1 ;
        RECT 0.183 0.018 0.195 0.078 ;
    END
  END E
  PIN Y
    DIRECTION OUTPUT ;
    USE SIGNAL ;
    PORT
      LAYER M1 ;
        POLYGON 0.237 0.102 0.237 0.018 0.225 0.018 0.225 0.09 0.141 0.09 0.141 0.102 ;
    END
  END Y
  PIN VDD
    DIRECTION INOUT ;
    USE POWER ;
    PORT
      LAYER M1 ;
        RECT -0.009 0.114 0.261 0.126 ;
    END
  END VDD
  PIN VSS
    DIRECTION INOUT ;
    USE GROUND ;
    PORT
      LAYER M1 ;
        RECT -0.009 -0.006 0.261 0.006 ;
    END
  END VSS
  OBS
    LAYER M1 ;
      RECT 0.057 0.018 0.153 0.03 ;
  END
END OAI311x1

MACRO OAI31x1
  CLASS CORE ;
  FOREIGN OAI31x1 ;
  ORIGIN 0 0 ;
  SIZE 0.21 BY 0.144 ;
  SYMMETRY X Y ;
  SITE core ;
  PIN A
    DIRECTION INPUT ;
    USE SIGNAL ;
    PORT
      LAYER M1 ;
        RECT 0.015 0.018 0.027 0.102 ;
    END
  END A
  PIN B
    DIRECTION INPUT ;
    USE SIGNAL ;
    PORT
      LAYER M1 ;
        RECT 0.057 0.042 0.069 0.102 ;
    END
  END B
  PIN C
    DIRECTION INPUT ;
    USE SIGNAL ;
    PORT
      LAYER M1 ;
        RECT 0.099 0.042 0.111 0.102 ;
    END
  END C
  PIN D
    DIRECTION INPUT ;
    USE SIGNAL ;
    PORT
      LAYER M1 ;
        RECT 0.141 0.042 0.153 0.078 ;
    END
  END D
  PIN Y
    DIRECTION OUTPUT ;
    USE SIGNAL ;
    PORT
      LAYER M1 ;
        POLYGON 0.195 0.102 0.195 0.018 0.183 0.018 0.183 0.09 0.141 0.09 0.141 0.102 ;
    END
  END Y
  PIN VDD
    DIRECTION INOUT ;
    USE POWER ;
    PORT
      LAYER M1 ;
        RECT -0.009 0.114 0.219 0.126 ;
    END
  END VDD
  PIN VSS
    DIRECTION INOUT ;
    USE GROUND ;
    PORT
      LAYER M1 ;
        RECT -0.009 -0.006 0.219 0.006 ;
    END
  END VSS
  OBS
    LAYER M1 ;
      RECT 0.057 0.018 0.153 0.03 ;
  END
END OAI31x1

MACRO OR2x1
  CLASS CORE ;
  FOREIGN OR2x1 ;
  ORIGIN 0 0 ;
  SIZE 0.21 BY 0.144 ;
  SYMMETRY X Y ;
  SITE core ;
  PIN A
    DIRECTION INPUT ;
    USE SIGNAL ;
    PORT
      LAYER M1 ;
        RECT 0.015 0.018 0.027 0.102 ;
    END
  END A
  PIN B
    DIRECTION INPUT ;
    USE SIGNAL ;
    PORT
      LAYER M1 ;
        RECT 0.099 0.018 0.111 0.078 ;
    END
  END B
  PIN Y
    DIRECTION OUTPUT ;
    USE SIGNAL ;
    PORT
      LAYER M1 ;
        RECT 0.183 0.018 0.195 0.102 ;
    END
  END Y
  PIN VDD
    DIRECTION INOUT ;
    USE POWER ;
    PORT
      LAYER M1 ;
        RECT -0.009 0.114 0.219 0.126 ;
    END
  END VDD
  PIN VSS
    DIRECTION INOUT ;
    USE GROUND ;
    PORT
      LAYER M1 ;
        RECT -0.009 -0.006 0.219 0.006 ;
    END
  END VSS
  OBS
    LAYER M1 ;
      POLYGON 0.153 0.102 0.153 0.054 0.141 0.054 0.141 0.09 0.069 0.09 0.069 0.024 0.057 0.024 0.057 0.102 ;
  END
END OR2x1

MACRO OR3x1
  CLASS CORE ;
  FOREIGN OR3x1 ;
  ORIGIN 0 0 ;
  SIZE 0.252 BY 0.144 ;
  SYMMETRY X Y ;
  SITE core ;
  PIN A
    DIRECTION INPUT ;
    USE SIGNAL ;
    PORT
      LAYER M1 ;
        RECT 0.015 0.018 0.027 0.102 ;
    END
  END A
  PIN B
    DIRECTION INPUT ;
    USE SIGNAL ;
    PORT
      LAYER M1 ;
        RECT 0.057 0.042 0.069 0.102 ;
    END
  END B
  PIN C
    DIRECTION INPUT ;
    USE SIGNAL ;
    PORT
      LAYER M1 ;
        RECT 0.099 0.042 0.111 0.102 ;
    END
  END C
  PIN Y
    DIRECTION OUTPUT ;
    USE SIGNAL ;
    PORT
      LAYER M1 ;
        RECT 0.225 0.018 0.237 0.102 ;
    END
  END Y
  PIN VDD
    DIRECTION INOUT ;
    USE POWER ;
    PORT
      LAYER M1 ;
        RECT -0.009 0.114 0.261 0.126 ;
    END
  END VDD
  PIN VSS
    DIRECTION INOUT ;
    USE GROUND ;
    PORT
      LAYER M1 ;
        RECT -0.009 -0.006 0.261 0.006 ;
    END
  END VSS
  OBS
    LAYER M1 ;
      POLYGON 0.153 0.096 0.153 0.066 0.195 0.066 0.195 0.054 0.153 0.054 0.153 0.018 0.057 0.018 0.057 0.03 0.141 0.03 0.141 0.096 ;
  END
END OR3x1

MACRO OR4x1
  CLASS CORE ;
  FOREIGN OR4x1 ;
  ORIGIN 0 0 ;
  SIZE 0.294 BY 0.144 ;
  SYMMETRY X Y ;
  SITE core ;
  PIN A
    DIRECTION INPUT ;
    USE SIGNAL ;
    PORT
      LAYER M1 ;
        RECT 0.015 0.018 0.027 0.102 ;
    END
  END A
  PIN B
    DIRECTION INPUT ;
    USE SIGNAL ;
    PORT
      LAYER M1 ;
        RECT 0.057 0.042 0.069 0.102 ;
    END
  END B
  PIN C
    DIRECTION INPUT ;
    USE SIGNAL ;
    PORT
      LAYER M1 ;
        RECT 0.099 0.042 0.111 0.102 ;
    END
  END C
  PIN D
    DIRECTION INPUT ;
    USE SIGNAL ;
    PORT
      LAYER M1 ;
        RECT 0.141 0.042 0.153 0.102 ;
    END
  END D
  PIN Y
    DIRECTION OUTPUT ;
    USE SIGNAL ;
    PORT
      LAYER M1 ;
        RECT 0.267 0.018 0.279 0.102 ;
    END
  END Y
  PIN VDD
    DIRECTION INOUT ;
    USE POWER ;
    PORT
      LAYER M1 ;
        RECT -0.009 0.114 0.303 0.126 ;
    END
  END VDD
  PIN VSS
    DIRECTION INOUT ;
    USE GROUND ;
    PORT
      LAYER M1 ;
        RECT -0.009 -0.006 0.303 0.006 ;
    END
  END VSS
  OBS
    LAYER M1 ;
      POLYGON 0.195 0.096 0.195 0.066 0.237 0.066 0.237 0.054 0.195 0.054 0.195 0.018 0.057 0.018 0.057 0.03 0.183 0.03 0.183 0.096 ;
  END
END OR4x1

MACRO XNOR2x1
  CLASS CORE ;
  FOREIGN XNOR2x1 ;
  ORIGIN 0 0 ;
  SIZE 0.378 BY 0.144 ;
  SYMMETRY X Y ;
  SITE core ;
  PIN A
    DIRECTION INPUT ;
    USE SIGNAL ;
    PORT
      LAYER M1 ;
        POLYGON 0.027 0.102 0.027 0.054 0.132 0.054 0.132 0.042 0.027 0.042 0.027 0.018 0.015 0.018 0.015 0.102 ;
    END
  END A
  PIN B
    DIRECTION INPUT ;
    USE SIGNAL ;
    PORT
      LAYER M1 ;
        POLYGON 0.363 0.102 0.363 0.018 0.246 0.018 0.246 0.03 0.351 0.03 0.351 0.09 0.162 0.09 0.162 0.102 ;
    END
  END B
  PIN Y
    DIRECTION OUTPUT ;
    USE SIGNAL ;
    PORT
      LAYER M1 ;
        POLYGON 0.132 0.102 0.132 0.078 0.195 0.078 0.195 0.066 0.12 0.066 0.12 0.102 ;
    END
  END Y
  PIN VDD
    DIRECTION INOUT ;
    USE POWER ;
    PORT
      LAYER M1 ;
        RECT -0.009 0.114 0.387 0.126 ;
    END
  END VDD
  PIN VSS
    DIRECTION INOUT ;
    USE GROUND ;
    PORT
      LAYER M1 ;
        RECT -0.009 -0.006 0.387 0.006 ;
    END
  END VSS
  OBS
    LAYER M1 ;
      POLYGON 0.321 0.078 0.321 0.066 0.237 0.066 0.237 0.042 0.162 0.042 0.162 0.054 0.225 0.054 0.225 0.078 ;
      RECT 0.057 0.018 0.216 0.03 ;
  END
  PROPERTY stopLevel 0 ;
  PROPERTY startLevel 0 ;
  PROPERTY snapMode "orthogonal" ;
  PROPERTY segSnapMode "orthogonal" ;
  PROPERTY pathCL "yes" ;
  PROPERTY lppVisibilityMode "donotCheckValidity" ;
  PROPERTY instanceDrawingMode "BBox" ;
  PROPERTY autoZoomScale 90 ;
  PROPERTY gridSpacing 1 ;
  PROPERTY xSnapSpacing 0.001 ;
  PROPERTY autoZoomMode "Pan" ;
  PROPERTY mergeScope "pcells" ;
  PROPERTY gridMultiple 5 ;
  PROPERTY arrayDisplay "Full" ;
  PROPERTY scrollPercent 25 ;
  PROPERTY displayResolution "Medium" ;
  PROPERTY instLabel "master" ;
  PROPERTY ySnapSpacing 0.001 ;
  PROPERTY filterSize 6 ;
  PROPERTY dimmingIntensity 50 ;
  PROPERTY filterSizeDrawingStyle "empty" ;
  PROPERTY dimmingScope "none" ;
END XNOR2x1

MACRO XNOR3x1
  CLASS CORE ;
  FOREIGN XNOR3x1 ;
  ORIGIN 0 0 ;
  SIZE 0.63 BY 0.144 ;
  SYMMETRY X Y ;
  SITE core ;
  PIN A
    DIRECTION INPUT ;
    USE SIGNAL ;
    PORT
      LAYER M1 ;
        POLYGON 0.048 0.102 0.048 0.054 0.09 0.054 0.09 0.042 0.036 0.042 0.036 0.102 ;
    END
  END A
  PIN B
    DIRECTION INPUT ;
    USE SIGNAL ;
    PORT
      LAYER M1 ;
        POLYGON 0.342 0.078 0.342 0.054 0.384 0.054 0.384 0.042 0.33 0.042 0.33 0.078 ;
    END
  END B
  PIN C
    DIRECTION INPUT ;
    USE SIGNAL ;
    PORT
      LAYER M1 ;
        POLYGON 0.615 0.102 0.615 0.018 0.498 0.018 0.498 0.03 0.603 0.03 0.603 0.09 0.414 0.09 0.414 0.102 ;
    END
  END C
  PIN Y
    DIRECTION OUTPUT ;
    USE SIGNAL ;
    PORT
      LAYER M1 ;
        POLYGON 0.09 0.102 0.09 0.078 0.153 0.078 0.153 0.066 0.078 0.066 0.078 0.102 ;
    END
  END Y
  PIN VDD
    DIRECTION INOUT ;
    USE POWER ;
    PORT
      LAYER M1 ;
        RECT -0.009 0.114 0.639 0.126 ;
    END
  END VDD
  PIN VSS
    DIRECTION INOUT ;
    USE GROUND ;
    PORT
      LAYER M1 ;
        RECT -0.009 -0.006 0.639 0.006 ;
    END
  END VSS
  OBS
    LAYER M1 ;
      POLYGON 0.384 0.102 0.384 0.078 0.447 0.078 0.447 0.066 0.372 0.066 0.372 0.09 0.12 0.09 0.12 0.102 ;
      POLYGON 0.572 0.078 0.572 0.066 0.489 0.066 0.489 0.042 0.414 0.042 0.414 0.054 0.477 0.054 0.477 0.078 ;
      POLYGON 0.279 0.078 0.279 0.066 0.195 0.066 0.195 0.042 0.12 0.042 0.12 0.054 0.183 0.054 0.183 0.078 ;
      RECT 0.309 0.018 0.468 0.03 ;
      RECT 0.204 0.018 0.258 0.03 ;
      RECT 0.015 0.018 0.174 0.03 ;
  END
END XNOR3x1

MACRO XOR2x1
  CLASS CORE ;
  FOREIGN XOR2x1 ;
  ORIGIN 0 0 ;
  SIZE 0.378 BY 0.144 ;
  SYMMETRY X Y ;
  SITE core ;
  PIN A
    DIRECTION INPUT ;
    USE SIGNAL ;
    PORT
      LAYER M1 ;
        POLYGON 0.027 0.102 0.027 0.054 0.132 0.054 0.132 0.042 0.027 0.042 0.027 0.018 0.015 0.018 0.015 0.102 ;
    END
  END A
  PIN B
    DIRECTION INPUT ;
    USE SIGNAL ;
    PORT
      LAYER M1 ;
        POLYGON 0.363 0.102 0.363 0.018 0.351 0.018 0.351 0.066 0.237 0.066 0.237 0.042 0.162 0.042 0.162 0.054 0.225 0.054 0.225 0.078 0.351 0.078 0.351 0.102 ;
    END
  END B
  PIN Y
    DIRECTION OUTPUT ;
    USE SIGNAL ;
    PORT
      LAYER M1 ;
        POLYGON 0.132 0.102 0.132 0.078 0.195 0.078 0.195 0.066 0.12 0.066 0.12 0.102 ;
    END
  END Y
  PIN VDD
    DIRECTION INOUT ;
    USE POWER ;
    PORT
      LAYER M1 ;
        RECT -0.009 0.114 0.387 0.126 ;
    END
  END VDD
  PIN VSS
    DIRECTION INOUT ;
    USE GROUND ;
    PORT
      LAYER M1 ;
        RECT -0.009 -0.006 0.387 0.006 ;
    END
  END VSS
  OBS
    LAYER M1 ;
      RECT 0.162 0.09 0.321 0.102 ;
      RECT 0.246 0.018 0.321 0.03 ;
      RECT 0.057 0.018 0.216 0.03 ;
  END
  PROPERTY stopLevel 0 ;
  PROPERTY startLevel 0 ;
  PROPERTY snapMode "orthogonal" ;
  PROPERTY segSnapMode "orthogonal" ;
  PROPERTY pathCL "yes" ;
  PROPERTY lppVisibilityMode "donotCheckValidity" ;
  PROPERTY instanceDrawingMode "BBox" ;
  PROPERTY autoZoomScale 90 ;
  PROPERTY gridSpacing 1 ;
  PROPERTY xSnapSpacing 0.001 ;
  PROPERTY autoZoomMode "Pan" ;
  PROPERTY mergeScope "pcells" ;
  PROPERTY gridMultiple 5 ;
  PROPERTY arrayDisplay "Full" ;
  PROPERTY scrollPercent 25 ;
  PROPERTY displayResolution "Medium" ;
  PROPERTY instLabel "master" ;
  PROPERTY ySnapSpacing 0.001 ;
  PROPERTY filterSize 6 ;
  PROPERTY dimmingIntensity 50 ;
  PROPERTY filterSizeDrawingStyle "empty" ;
  PROPERTY dimmingScope "none" ;
END XOR2x1

MACRO XOR3x1
  CLASS CORE ;
  FOREIGN XOR3x1 ;
  ORIGIN 0 0 ;
  SIZE 0.63 BY 0.144 ;
  SYMMETRY X Y ;
  SITE core ;
  PIN A
    DIRECTION INPUT ;
    USE SIGNAL ;
    PORT
      LAYER M1 ;
        POLYGON 0.048 0.102 0.048 0.054 0.09 0.054 0.09 0.042 0.036 0.042 0.036 0.102 ;
    END
  END A
  PIN B
    DIRECTION INPUT ;
    USE SIGNAL ;
    PORT
      LAYER M1 ;
        POLYGON 0.363 0.078 0.363 0.054 0.384 0.054 0.384 0.042 0.33 0.042 0.33 0.054 0.351 0.054 0.351 0.078 ;
    END
  END B
  PIN C
    DIRECTION INPUT ;
    USE SIGNAL ;
    PORT
      LAYER M1 ;
        POLYGON 0.615 0.102 0.615 0.018 0.603 0.018 0.603 0.066 0.489 0.066 0.489 0.042 0.414 0.042 0.414 0.054 0.477 0.054 0.477 0.078 0.603 0.078 0.603 0.102 ;
    END
  END C
  PIN Y
    DIRECTION OUTPUT ;
    USE SIGNAL ;
    PORT
      LAYER M1 ;
        POLYGON 0.09 0.102 0.09 0.078 0.153 0.078 0.153 0.066 0.078 0.066 0.078 0.102 ;
    END
  END Y
  PIN VDD
    DIRECTION INOUT ;
    USE POWER ;
    PORT
      LAYER M1 ;
        RECT -0.009 0.114 0.639 0.126 ;
    END
  END VDD
  PIN VSS
    DIRECTION INOUT ;
    USE GROUND ;
    PORT
      LAYER M1 ;
        RECT -0.009 -0.006 0.639 0.006 ;
    END
  END VSS
  OBS
    LAYER M1 ;
      RECT 0.414 0.09 0.573 0.102 ;
      POLYGON 0.395 0.102 0.395 0.078 0.447 0.078 0.447 0.066 0.383 0.066 0.383 0.09 0.321 0.09 0.321 0.066 0.195 0.066 0.195 0.042 0.12 0.042 0.12 0.054 0.183 0.054 0.183 0.078 0.309 0.078 0.309 0.102 ;
      RECT 0.12 0.09 0.279 0.102 ;
      RECT 0.498 0.018 0.573 0.03 ;
      RECT 0.309 0.018 0.468 0.03 ;
      RECT 0.204 0.018 0.279 0.03 ;
      RECT 0.015 0.018 0.174 0.03 ;
  END
  PROPERTY stopLevel 0 ;
  PROPERTY startLevel 0 ;
  PROPERTY snapMode "orthogonal" ;
  PROPERTY segSnapMode "orthogonal" ;
  PROPERTY pathCL "yes" ;
  PROPERTY lppVisibilityMode "donotCheckValidity" ;
  PROPERTY instanceDrawingMode "BBox" ;
  PROPERTY autoZoomScale 90 ;
  PROPERTY gridSpacing 1 ;
  PROPERTY xSnapSpacing 0.001 ;
  PROPERTY autoZoomMode "Pan" ;
  PROPERTY mergeScope "pcells" ;
  PROPERTY gridMultiple 5 ;
  PROPERTY arrayDisplay "Full" ;
  PROPERTY scrollPercent 25 ;
  PROPERTY displayResolution "Medium" ;
  PROPERTY instLabel "master" ;
  PROPERTY ySnapSpacing 0.001 ;
  PROPERTY filterSize 6 ;
  PROPERTY dimmingIntensity 50 ;
  PROPERTY filterSizeDrawingStyle "empty" ;
  PROPERTY dimmingScope "none" ;
END XOR3x1

END LIBRARY
